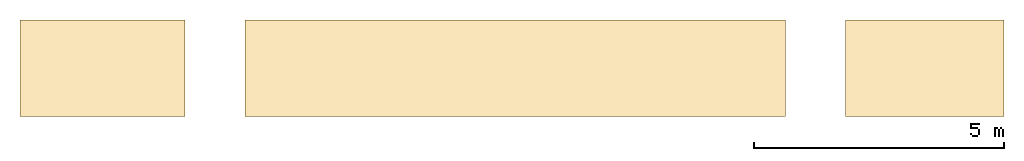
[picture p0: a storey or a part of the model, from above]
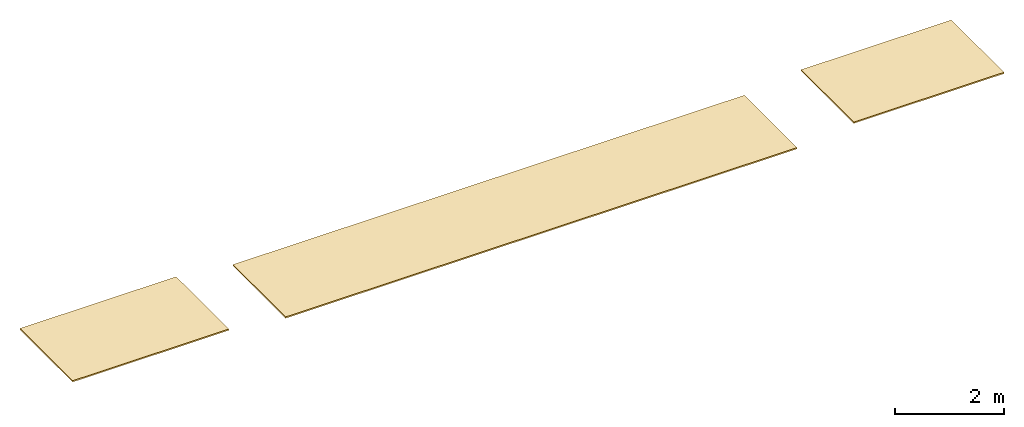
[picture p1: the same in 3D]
Properties of the parts of a building model (IFC2X3), part 1 of 3

# File
Description: ViewDefinition [CoordinationView]
File name: gmtio-a-200-1-0001.ifc (Edited by Naviate Simple BIM 2022 version 6)
Time: 2026-03-17T17:15:05+01:00
Written by: ODA SDAI 24.12
Made in: Autodesk Revit 25.4.20.11 (ENU) - IFC 25.4.0.27

# IfcProject, A181143
LongName: T2; Phase: Detaljprosjekt

# IfcSite (7)
Name | RefLatitude | RefLongitude | RefElevation (mm) | Reference latitude | Reference elevation | Reference longitude
ENGM | 33, 12, 51, 119999 | -97, -7, -51, -239999 | -4.85124e-10
Gardermoen
ENGM | 33, 12, 51, 119999 | -97, -7, -51, -239999 | 0 | 33, 12, 51, 119999 | 0 | -97, -7, -51, -239999 | MagiCAD Pset_Site - Name: ENGM
ENGM | 59, 54, 49, 759826 | 10, 44, 19, 467315 | 0 | 59, 54, 49, 759826 | 0 | 10, 44, 19, 467315 | MagiCAD Pset_Site - Name: ENGM
ENGM | 42, 24, 53, 508911 | -71, -15, -29, -58837 | 0 | 42, 24, 53, 508911 | 0 | -71, -15, -29, -58837 | MagiCAD Pset_Site - Name: ENGM
Default | 59, 54, 57, 599999 | 10, 44, 59, 999999 | 0
 | 33, 12, 51, 119998 | -97, -7, -51, -239998 | 0 | 33, 12, 51, 119998 | 0 | -97, -7, -51, -239998

# IfcBuilding (7)
Name
TI | LongName: TI; Pset_BuildingCommon - BuildingID: TI; NumberOfStoreys: 15
TI
3 x TI | MagiCAD Pset_Building - Building name: TI
 | Pset_BuildingCommon - NumberOfStoreys: 3; Pset_ProductRequirements - Category: Project Information
mc-building

# IfcBuildingStorey (12)
Name | In | Elevation (mm) | Name
D | TI | 0
F | TI | 0
3 x Nivå F | TI | 210900 | Nivå F
Nivå D + 1,2 m | TI | 205200 | Nivå D + 1,2 m
2 x Nivå E | TI | 207370 | Nivå E
Nivå D | TI | 204000 | Nivå D
Nivå D | mc-building | 204000 | Nivå D
Nivå D + 1,2 m | mc-building | 205200 | Nivå D + 1,2 m
Nivå F -0,7 | mc-building | 210200 | Nivå F -0,7

# IfcBuildingStorey: Level:8mm Head, Nivå E
LongName: Nivå E; Elevation: 207370 mm
Pset_ProductRequirements - Name: Nivå E; Category: Levels
Pset_AirSideSystemInformation - Name: Nivå E

# IfcBuildingStorey: Level:T2 - Kote (3)
In: TI
Name | LongName | Elevation (mm) | Pset_ProductRequirements, Name | Pset_ProductRequirements, sets with these values
Nivå D | Nivå D | 204000 | Pset_AirSideSystemInformation - Name: Nivå D; sets with these values: 2
Nivå F | Nivå F | 210900 | Nivå F | 2
Nivå G - 2,0m | Nivå G - 2,0m | 213700 | Nivå G - 2,0m | 2

# IfcBeam: DLB500*1500-900*1235*880, PREFABBJELKE
In: F
Description: DLB500*1500-900*1235*880
ePset_SimplebimBasicQuantities - Area, sides, net (Simplebim): 2.27588 m2; Volume, net (Simplebim): 0.189349 m3; Weight, as steel (Simplebim): 1486.39 kg; Width (Simplebim): 383 mm; Length (Simplebim): 900 mm; Height (Simplebim): 780 mm
AVINOR - 08_Status: S4; 07_Fase: F40; 06_Omrade: TI; 05_ID-nummer: +TI=223.007; 03_Ansvar: 72242; 04_Kontrakt: 72242; 02_Prosjekt: T20100; 01_Lufthavnkode: ENGM
Tekla Common - Name: PREFABBJELKE; Bottom elevation: +209.180; Grade: C45/55; Profile: DLB500*1500-900*1235*880; Assembly mark: PB-277; Part mark: Concrete-7649; Top elevation: +210.680; Class: 130
ePset_Simplebim - Assembly Level: Leaf
ePset_LocationTool - Splitting: RESULT
Pset_BeamCommon - LoadBearing: no; Reference: Concrete-7649

# IfcBeam: GRID:A255 - Opphengsgrid - Profil med deksel over og under (5)
In: Nivå F
Type - PredefinedType: BEAM; Material: Default, Metal - Steel
Type - Pset_BeamCommon - LoadBearing: yes
Pset_QuantityTakeOff - Reference: A255 - Opphengsgrid - Profil med deksel over og under; sets with these values: 2
AVINOR - 08_Status: S4; 07_Fase: F90; 05_ID-nummer: +TI=255.002; 06_Omrade: TI; 03_Ansvar: 72717; 02_Prosjekt: x; 01_Lufthavnkode: ENGM
ePset_LocationTool - Splitting: ORIGINAL
Pset_BeamCommon - Reference: A255 - Opphengsgrid - Profil med deksel over og under; IsExternal: no; Slope: 0 deg
ePset_Simplebim - Assembly Level: Leaf
ePset_SimplebimBasicQuantities - Width (Simplebim): 40 mm; Height (Simplebim): 96 mm
Name (GRID:A255 - Opphengsgrid - Profil med deksel over og under:...) | Span (mm) = Length (Simplebim) (mm) | Volume, net (Simplebim) (m3) | Weight, as steel (Simplebim) (kg) | Area, sides, net (Simplebim) (m2)
64454443 | 16817.8 | 0.011563 | 90.7693 | 11.937
64454517 | 17918.5 | 0.0123197 | 96.7096 | 12.7182
66954951 | 15717.2 | 0.0108062 | 84.829 | 11.1559
66954953 | 14616.6 | 0.0100495 | 78.8887 | 10.3748
67121430 | 18774.5 | 0.0129083 | 101.33 | 13.3257

# IfcBeam: IPE140 (3)
In: F
Description: IPE140; Material: STEEL/S355
ePset_Simplebim - Assembly Level: Leaf
ePset_SimplebimBasicQuantities - Width (Simplebim): 73 mm; Height (Simplebim): 140 mm
AVINOR - 08_Status: S4; 07_Fase: F90; 06_Omrade: TI; 05_ID-nummer: +TI=221.038; 04_Kontrakt: 72717; 02_Prosjekt: T20100; 03_Ansvar: 72101; 01_Lufthavnkode: ENGM
Tekla Quantity - Width: 73 mm; Heigth: 140 mm
ePset_LocationTool - Splitting: ORIGINAL
Pset_BeamCommon - LoadBearing: no
Tekla Common - Grade: S355; Name: STÅLBJELKE; Profile: IPE140; Class: 330
Name | Area, sides, net (Simplebim) (m2) | Volume, net (Simplebim) (m3) | Weight, as steel (Simplebim) (kg) = WEIGTH_NET (kg) | Length (Simplebim) (mm) = Length (mm) | VOLUME_GROSS (m3) | WEIGTH_GROSS (kg) | AREA_NET (m2) | VOLUME_NET (m3) | AREA_GROSS (m2) | Reference = Part mark | Top elevation | Assembly mark | Bottom elevation
STÅLBJELKE | 0.0988618 | 0.000272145 | 2.13634 | 170.033 | 0.00028 | 2.18901 | 0.09885 | 0.00026 | 0.09369 | DSB-0(?) | +213.578 | SS-0(?) | +213.438
STÅLBJELKE | 0.764585 | 0.0021659 | 17.0023 | 1363.01 | 0.00224 | 17.5474 | 0.76459 | 0.00217 | 0.75102 | DSB-24028(?) | +213.578 | SB-14382(?) | +213.438
STÅLBJELKE | 1.37537 | 0.00390368 | 30.6439 | 2438.98 | 0.00399 | 31.3994 | 1.37537 | 0.0039 | 1.34388 | DSB-19527(?) | +213.438 | SB-11779(?) | +213.298

# IfcBeam: L150*100*10 (2)
In: F
Description: L150*100*10; Material: STEEL/S355J0
ePset_LocationTool - Splitting: ORIGINAL
ePset_SimplebimBasicQuantities - Length (Simplebim): 128.286 mm; Weight, as steel (Simplebim): 2.05585 kg; Volume, net (Simplebim): 0.000261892 m3; Width (Simplebim): 119.998 mm; Height (Simplebim): 100 mm; Area, sides, net (Simplebim): 0.0591433 m2
Tekla Quantity - Heigth: 128.286 mm; Length: 119.998 mm; VOLUME_GROSS: 0.00028 m3; AREA_NET: 0.05914 m2; AREA_GROSS: 0.05868 m2; WEIGTH_NET: 2.05585 kg; VOLUME_NET: 0.00026 m3; Width: 100 mm; WEIGTH_GROSS: 2.27961 kg
ePset_Simplebim - Assembly Level: Leaf
AVINOR - 08_Status: S4; 07_Fase: F90; 06_Omrade: TI; 05_ID-nummer: +TI=221.038; 04_Kontrakt: 72717; 02_Prosjekt: T20100; 03_Ansvar: 72101; 01_Lufthavnkode: ENGM
Tekla Common - Bottom elevation: +213.578; Name: STÅLBJELKE; Assembly mark: SB-11789(?); Profile: L150*100*10; Grade: S355J0; Part mark: DSB-0(?); Top elevation: +213.678; Class: 330
Pset_BeamCommon - LoadBearing: no; Reference: DSB-0(?)

# IfcBeam: L150*90*9 (2)
In: F
Description: L150*90*9; Material: STEEL/S355
ePset_LocationTool - Splitting: ORIGINAL
ePset_Simplebim - Assembly Level: Leaf
Tekla Common - Grade: S355; Name: STÅLBJELKE; Bottom elevation: +213.405; Top elevation: +213.495; Profile: L150*90*9; Class: 330
AVINOR - 04_Kontrakt: 72253; 05_ID-nummer: +TI=221.025; 08_Status: S4; 07_Fase: F90; 06_Omrade: TI; 02_Prosjekt: T20100; 03_Ansvar: 72101; 01_Lufthavnkode: ENGM
ePset_SimplebimBasicQuantities - Height (Simplebim): 90 mm
Pset_BeamCommon - LoadBearing: no
Tekla Quantity - VOLUME_NET: 0.00034 m3; AREA_NET: 0.08296 m2; VOLUME_GROSS: 0.00039 m3; Width: 90 mm; AREA_GROSS: 0.09536 m2
Name | Assembly mark | Part mark = Reference | Width (Simplebim) (mm) = Heigth (mm) | Weight, as steel (Simplebim) (kg) = WEIGTH_NET (kg) | Volume, net (Simplebim) (m3) | Length (Simplebim) (mm) = Length (mm) | Area, sides, net (Simplebim) (m2) | WEIGTH_GROSS (kg)
STÅLBJELKE | SB-14628(?) | DSB-24528(?) | 147.671 | 2.6797 | 0.000341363 | 189.996 | 0.0829498 | 3.10076
STÅLBJELKE | SB-14629(?) | DSB-24529(?) | 147.673 | 2.67982 | 0.000341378 | 190.008 | 0.0829534 | 3.10097

# IfcBeam: L75*8 (6)
In: F
Description: L75*8; Material: STEEL/S355J0
Tekla Common - Bottom elevation: +213.578; Profile: L75*8; Name: STÅLBJELKE; Top elevation: +213.653; Grade: S355J0; Part mark: DSB-0(?); Class: 330
ePset_Simplebim - Assembly Level: Leaf
Tekla Quantity - Heigth: 75 mm; Width: 75 mm
AVINOR - 08_Status: S4; 07_Fase: F90; 06_Omrade: TI; 05_ID-nummer: +TI=221.038; 04_Kontrakt: 72717; 02_Prosjekt: T20100; 03_Ansvar: 72101; 01_Lufthavnkode: ENGM
ePset_SimplebimBasicQuantities - Height (Simplebim): 75 mm; Width (Simplebim): 75 mm
Pset_BeamCommon - LoadBearing: no; Reference: DSB-0(?)
ePset_LocationTool - Splitting: ORIGINAL
Name | Assembly mark | VOLUME_NET (m3) | VOLUME_GROSS (m3) | AREA_GROSS (m2) | WEIGTH_GROSS (kg) | WEIGTH_NET (kg) = Weight, as steel (Simplebim) (kg) | Length (mm) = Length (Simplebim) (mm) | AREA_NET (m2) | Area, sides, net (Simplebim) (m2) | Volume, net (Simplebim) (m3)
STÅLBJELKE | SB-11777(?) | 0.00022 | 0.00022 | 0.0582 | 1.80556 | 1.78358 | 200.006 | 0.06227 | 0.0622739 | 0.000227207
STÅLBJELKE | SB-11777(?) | 0.00017 | 0.00017 | 0.04365 | 1.35411 | 1.33762 | 149.998 | 0.04727 | 0.0472715 | 0.000170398
2 x STÅLBJELKE | SB-11789(?) | 0.00017 | 0.00017 | 0.04365 | 1.35411 | 1.33762 | 149.998 | 0.04727 | 0.0472715 | 0.000170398
STÅLBJELKE | SB-11779(?) | 0.00011 | 0.00013 | 0.0291 | 0.90275 | 0.89176 | 100 | 0.03227 | 0.032272 | 0.0001136
STÅLBJELKE | SB-11779(?) | 0.00011 | 0.00011 | 0.0291 | 0.90275 | 0.89176 | 100 | 0.03227 | 0.032272 | 0.0001136

# IfcBeam: L90*150*9 (2)
In: F
Description: L90*150*9; Material: STEEL/S355
ePset_SimplebimBasicQuantities - Volume, net (Simplebim): 0.000341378 m3; Area, sides, net (Simplebim): 0.0829534 m2; Length (Simplebim): 190.008 mm; Width (Simplebim): 147.673 mm; Weight, as steel (Simplebim): 2.67982 kg; Height (Simplebim): 90 mm
Tekla Quantity - Length: 190.008 mm; VOLUME_NET: 0.00034 m3; AREA_NET: 0.08296 m2; Width: 147.673 mm; VOLUME_GROSS: 0.00039 m3; WEIGTH_GROSS: 3.10097 kg; WEIGTH_NET: 2.67982 kg; Heigth: 90 mm; AREA_GROSS: 0.09536 m2
ePset_Simplebim - Assembly Level: Leaf
Pset_BeamCommon - LoadBearing: no
AVINOR - 04_Kontrakt: 72253; 05_ID-nummer: +TI=221.025; 08_Status: S4; 07_Fase: F90; 06_Omrade: TI; 02_Prosjekt: T20100; 03_Ansvar: 72101; 01_Lufthavnkode: ENGM
ePset_LocationTool - Splitting: ORIGINAL
Tekla Common - Grade: S355; Bottom elevation: +213.805; Top elevation: +213.895; Name: STÅLBJELKE; Profile: L90*150*9; Class: 330
Name | Reference = Part mark | Assembly mark
STÅLBJELKE | DSB-24527(?) | SB-14627(?)
STÅLBJELKE | DSB-24526(?) | SB-14626(?)

# IfcBeam: L90*9 (148)
In: F
Description: L90*9; Material: STEEL/S355
ePset_SimplebimBasicQuantities - Height (Simplebim): 90 mm
ePset_Simplebim - Assembly Level: Leaf
ePset_LocationTool - Splitting: ORIGINAL
AVINOR - 04_Kontrakt: 72253; 05_ID-nummer: +TI=221.025; 08_Status: S4; 07_Fase: F90; 06_Omrade: TI; 02_Prosjekt: T20100; 03_Ansvar: 72101; 01_Lufthavnkode: ENGM
Tekla Common - Profile: L90*9; Grade: S355; Name: STÅLBJELKE; Class: 330
Tekla Quantity - VOLUME_NET: 0.00022 m3
Pset_BeamCommon - LoadBearing: no
Name | Volume, net (Simplebim) (m3) | Weight, as steel (Simplebim) (kg) | Width (Simplebim) (mm) | Area, sides, net (Simplebim) (m2) | Length (Simplebim) (mm) | Assembly mark | Part mark = Reference | Bottom elevation | Top elevation | AREA_GROSS (m2) | VOLUME_GROSS (m3) | Heigth (mm) | WEIGTH_GROSS (kg) | Width (mm) | AREA_NET (m2) | Length (mm) | WEIGTH_NET (kg)
STÅLBJELKE | 0.000226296 | 1.77642 | 80.3791 | 0.0561683 | 190.006 | SB-11832(?) | DSB-19626(?) | +213.405 | +213.495 | 0.06669 | 0.00028 | 80.3791 | 2.3119 | 90 | 0.05617 | 190.006 | 1.77642
STÅLBJELKE | 0.000226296 | 1.77642 | 80.3791 | 0.0561683 | 190.006 | SB-11833(?) | DSB-19627(?) | +213.805 | +213.895 | 0.06669 | 0.00028 | 90 | 2.3119 | 80.3791 | 0.05617 | 190.006 | 1.77642
STÅLBJELKE | 0.000226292 | 1.77639 | 80.3766 | 0.0561673 | 190.006 | SB-11833(?) | DSB-19627(?) | +213.405 | +213.495 | 0.06669 | 0.00028 | 80.3766 | 2.3119 | 90 | 0.05617 | 190.006 | 1.77639
STÅLBJELKE | 0.000226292 | 1.77639 | 80.3766 | 0.0561673 | 190.006 | SB-11832(?) | DSB-19626(?) | +213.805 | +213.895 | 0.06669 | 0.00028 | 90 | 2.3119 | 80.3766 | 0.05617 | 190.006 | 1.77639
29 x STÅLBJELKE | 0.00023085 | 1.81217 | 90 | 0.057078 | 150 | SB-11830(?) | DSB-19624(?) | +213.405 | +213.495 | 0.05265 | 0.00022 | 90 | 1.82506 | 90 | 0.05708 | 149.995 | 1.81211
29 x STÅLBJELKE | 0.00023085 | 1.81217 | 90 | 0.057078 | 150 | SB-11830(?) | DSB-19624(?) | +213.805 | +213.895 | 0.05265 | 0.00022 | 90 | 1.82506 | 90 | 0.05708 | 149.995 | 1.81211
7 x STÅLBJELKE | 0.00023085 | 1.81217 | 90 | 0.057078 | 150 | SB-11830(?) | DSB-19624(?) | +213.405 | +213.495 | 0.05265 | 0.00022 | 90 | 1.82529 | 90 | 0.05708 | 150.014 | 1.81234
7 x STÅLBJELKE | 0.00023085 | 1.81217 | 90 | 0.057078 | 150 | SB-11830(?) | DSB-19624(?) | +213.805 | +213.895 | 0.05265 | 0.00022 | 90 | 1.82529 | 90 | 0.05708 | 150.014 | 1.81234
36 x STÅLBJELKE | 0.00023085 | 1.81217 | 90 | 0.057078 | 150 | SB-11830(?) | DSB-19624(?) | +213.405 | +213.495 | 0.05265 | 0.00022 | 90 | 1.82512 | 90 | 0.05708 | 150 | 1.81217
36 x STÅLBJELKE | 0.00023085 | 1.81217 | 90 | 0.057078 | 150 | SB-11830(?) | DSB-19624(?) | +213.805 | +213.895 | 0.05265 | 0.00022 | 90 | 1.82512 | 90 | 0.05708 | 150 | 1.81217

# IfcBeam: PL10*180, STÅLBJELKE
In: F
Description: PL10*180; Material: STEEL/S355J0
Tekla Common - Name: STÅLBJELKE; Top elevation: +213.693; Bottom elevation: +213.513; Grade: S355J0; Part mark: DSB-0(?); Profile: PL10*180; Class: 330; Assembly mark: SB-11777(?)
ePset_SimplebimBasicQuantities - Area, sides, net (Simplebim): 0.0529974 m2; Weight, as steel (Simplebim): 1.8368 kg; Height (Simplebim): 180 mm; Width (Simplebim): 10 mm; Length (Simplebim): 129.993 mm; Volume, net (Simplebim): 0.000233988 m3
ePset_Simplebim - Assembly Level: Leaf
AVINOR - 08_Status: S4; 07_Fase: F90; 06_Omrade: TI; 05_ID-nummer: +TI=221.038; 04_Kontrakt: 72717; 02_Prosjekt: T20100; 03_Ansvar: 72101; 01_Lufthavnkode: ENGM
Pset_BeamCommon - LoadBearing: no; Reference: DSB-0(?)
ePset_LocationTool - Splitting: ORIGINAL
Tekla Quantity - VOLUME_NET: 0.00022 m3; VOLUME_GROSS: 0.00022 m3; AREA_GROSS: 0.053 m2; AREA_NET: 0.053 m2; Width: 10 mm; Heigth: 180 mm; WEIGTH_GROSS: 1.8368 kg; WEIGTH_NET: 1.8368 kg; Length: 129.993 mm

# IfcBeam: PL10*490 (10)
In: F
Description: PL10*490; Material: STEEL/S355
ePset_SimplebimBasicQuantities - Height (Simplebim): 490 mm
Pset_BeamCommon - LoadBearing: no
ePset_Simplebim - Assembly Level: Leaf
Tekla Quantity - Heigth: 490 mm
ePset_LocationTool - Splitting: ORIGINAL
AVINOR - 04_Kontrakt: 72253; 05_ID-nummer: +TI=221.025; 08_Status: S4; 07_Fase: F90; 06_Omrade: TI; 02_Prosjekt: T20100; 03_Ansvar: 72101; 01_Lufthavnkode: ENGM
Tekla Common - Grade: S355; Top elevation: +213.895; Name: STÅLBJELKE; Profile: PL10*490; Bottom elevation: +213.405; Class: 330
Name | Volume, net (Simplebim) (m3) | Width (Simplebim) (mm) | Length (Simplebim) (mm) | Area, sides, net (Simplebim) (m2) | Weight, as steel (Simplebim) (kg) | Reference = Part mark | Length (mm) | WEIGTH_NET (kg) | AREA_GROSS (m2) | AREA_NET (m2) | Width (mm) | VOLUME_NET (m3) | VOLUME_GROSS (m3) | WEIGTH_GROSS (kg) | Assembly mark
STÅLBJELKE | 0.00416928 | 200.017 | 619.575 | 0.866946 | 32.7289 | DSS-5676(?) | 936.263 | 32.7285 | 0.94606 | 0.86695 | 10.0076 | 0.00416 | 0.00458 | 36.0133 | SS-8909(?)
STÅLBJELKE | 0.0038293 | 200.017 | 619.575 | 0.798947 | 30.06 | DSS-5677(?) | 936.263 | 30.0606 | 0.94606 | 0.79895 | 10.0076 | 0.00383 | 0.00458 | 36.0133 | SS-8910(?)
STÅLBJELKE | 0.021315 | 10 | 4350 | 4.3598 | 167.323 | DSS-5860(?) | 4350 | 167.323 | 4.3598 | 4.3598 | 10 | 0.02131 | 0.0213 | 167.323 | SS-9019(?)
2 x STÅLBJELKE | 0.02156 | 10 | 4400 | 4.4098 | 169.246 | DSS-5861(?) | 4400 | 169.246 | 4.4098 | 4.4098 | 10 | 0.02156 | 0.02156 | 169.246 | SS-9020(?)
STÅLBJELKE | 0.021315 | 10 | 4350 | 4.3598 | 167.323 | DSS-5860(?) | 4350 | 167.323 | 4.3598 | 4.3598 | 10 | 0.02131 | 0.02132 | 167.323 | SS-9019(?)
2 x STÅLBJELKE | 0.0208005 | 10 | 4245 | 4.2548 | 163.284 | DSS-5858(?) | 4245 | 163.284 | 4.2548 | 4.2548 | 10 | 0.0208 | 0.0208 | 163.284 | SS-9017(?)
2 x STÅLBJELKE | 0.0206045 | 10 | 4205 | 4.2148 | 161.745 | DSS-5857(?) | 4205 | 161.745 | 4.2148 | 4.2148 | 10 | 0.0206 | 0.0206 | 161.745 | SS-9016(?)

# IfcBeam: PL8*100 (11)
In: F
Description: PL8*100; Material: STEEL/S355
Tekla Common - Grade: S355; Name: STÅLBJELKE; Top elevation: +213.745; Profile: PL8*100; Bottom elevation: +213.737; Part mark: DSB-14986(?); Class: 330
Pset_BeamCommon - LoadBearing: no; Reference: DSB-14986(?)
ePset_LocationTool - Splitting: ORIGINAL
ePset_Simplebim - Assembly Level: Leaf
AVINOR - 04_Kontrakt: 72253; 05_ID-nummer: +TI=221.025; 08_Status: S4; 07_Fase: F90; 06_Omrade: TI; 02_Prosjekt: T20100; 03_Ansvar: 72101; 01_Lufthavnkode: ENGM
ePset_SimplebimBasicQuantities - Area, sides, net (Simplebim): 0.0448 m2; Volume, net (Simplebim): 0.00016 m3; Height (Simplebim): 8 mm; Width (Simplebim): 100 mm; Length (Simplebim): 200 mm; Weight, as steel (Simplebim): 1.256 kg
Tekla Quantity - AREA_NET: 0.0448 m2; VOLUME_GROSS: 0.00015 m3; VOLUME_NET: 0.00015 m3; Width: 8 mm; Heigth: 100 mm; Length: 200 mm; WEIGTH_NET: 1.256 kg; WEIGTH_GROSS: 1.256 kg; AREA_GROSS: 0.02 m2
Name | Assembly mark
2 x STÅLBJELKE | SS-7605(?)
STÅLBJELKE | SS-7611(?)
5 x STÅLBJELKE | SB-9013(?)
3 x STÅLBJELKE | SS-7612(?)

# IfcBeam: PL8*30 (4)
In: F
Description: PL8*30; Material: STEEL/S355
ePset_SimplebimBasicQuantities - Height (Simplebim): 126.2 mm; Weight, as steel (Simplebim): 0.231481 kg; Volume, net (Simplebim): 0.000029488 m3; Width (Simplebim): 8 mm; Length (Simplebim): 30 mm; Area, sides, net (Simplebim): 0.00977747 m2
Tekla Common - Profile: PL8*30; Grade: S355; Name: STÅLBJELKE; Part mark: DSB-0(?); Class: 330
ePset_Simplebim - Assembly Level: Leaf
AVINOR - 08_Status: S4; 07_Fase: F90; 06_Omrade: TI; 05_ID-nummer: +TI=221.038; 04_Kontrakt: 72717; 02_Prosjekt: T20100; 03_Ansvar: 72101; 01_Lufthavnkode: ENGM
ePset_LocationTool - Splitting: ORIGINAL
Pset_BeamCommon - LoadBearing: no; Reference: DSB-0(?)
Tekla Quantity - Length: 126.2 mm; WEIGTH_NET: 0.23148 kg; AREA_GROSS: 0.00379 m2; Width: 8 mm; Heigth: 30 mm; WEIGTH_GROSS: 0.23776 kg; AREA_NET: 0.00978 m2; VOLUME_GROSS: 0.00003 m3; VOLUME_NET: 0.00003 m3
Name | Assembly mark | Bottom elevation | Top elevation
2 x STÅLBJELKE | SB-14382(?) | +213.445 | +213.571
2 x STÅLBJELKE | SB-11779(?) | +213.305 | +213.431

# IfcBeam: PL8*85, STÅLBJELKE
In: F
Description: PL8*85; Material: STEEL/S355
ePset_SimplebimBasicQuantities - Area, sides, net (Simplebim): 0.05623 m2; Volume, net (Simplebim): 0.0002006 m3; Weight, as steel (Simplebim): 1.57471 kg; Height (Simplebim): 8 mm; Width (Simplebim): 85 mm; Length (Simplebim): 295 mm
ePset_Simplebim - Assembly Level: Leaf
AVINOR - 08_Status: S4; 07_Fase: F90; 06_Omrade: TI; 05_ID-nummer: +TI=221.038; 04_Kontrakt: 72717; 02_Prosjekt: T20100; 03_Ansvar: 72101; 01_Lufthavnkode: ENGM
Tekla Common - Grade: S355; Profile: PL8*85; Name: STÅLBJELKE; Assembly mark: SS-0(?); Part mark: DSB-0(?); Top elevation: +213.298; Class: 330; Bottom elevation: +213.290
Pset_BeamCommon - LoadBearing: no; Reference: DSB-0(?)
ePset_LocationTool - Splitting: ORIGINAL
Tekla Quantity - AREA_NET: 0.05623 m2; VOLUME_GROSS: 0.0002 m3; VOLUME_NET: 0.0002 m3; AREA_GROSS: 0.05622 m2; WEIGTH_GROSS: 1.57471 kg; WEIGTH_NET: 1.57471 kg; Width: 8 mm; Heigth: 85 mm; Length: 295 mm

# IfcBeam: RHS100*8, STÅLBJELKE
In: F
Description: RHS100*8; Material: STEEL/S355
Tekla Quantity - AREA_NET: 5.5511 m2; WEIGTH_GROSS: 317.524 kg; VOLUME_GROSS: 0.04045 m3; WEIGTH_NET: 320.527 kg; AREA_GROSS: 5.32369 m2; Length: 13900 mm; Heigth: 100 mm; Width: 100 mm; VOLUME_NET: 0.04083 m3
ePset_Simplebim - Assembly Level: Leaf
ePset_LocationTool - Splitting: ORIGINAL
Pset_BeamCommon - Reference: DSS-6695(?); LoadBearing: no
Tekla Common - Part mark: DSS-6695(?); Grade: S355; Top elevation: +213.895; Name: STÅLBJELKE; Profile: RHS100*8; Bottom elevation: +213.795; Assembly mark: SS-8144(?); Class: 330
ePset_SimplebimBasicQuantities - Weight, as steel (Simplebim): 320.527 kg; Length (Simplebim): 13900 mm; Width (Simplebim): 100 mm; Height (Simplebim): 100 mm; Volume, net (Simplebim): 0.0408315 m3; Area, sides, net (Simplebim): 10.214 m2
AVINOR - 04_Kontrakt: 72253; 05_ID-nummer: +TI=221.025; 08_Status: S4; 07_Fase: F90; 06_Omrade: TI; 02_Prosjekt: T20100; 03_Ansvar: 72101; 01_Lufthavnkode: ENGM

# IfcBeam: RHS120*80*6.3 (3)
In: F
Description: RHS120*80*6.3; Material: STEEL/S355
ePset_SimplebimBasicQuantities - Height (Simplebim): 120 mm; Width (Simplebim): 80 mm
Tekla Quantity - Width: 80 mm; Heigth: 120 mm
ePset_LocationTool - Splitting: ORIGINAL
ePset_Simplebim - Assembly Level: Leaf
Tekla Common - Grade: S355; Bottom elevation: +213.578; Name: STÅLBJELKE; Top elevation: +213.698; Profile: RHS120*80*6.3; Class: 330
AVINOR - 08_Status: S4; 07_Fase: F90; 06_Omrade: TI; 05_ID-nummer: +TI=221.038; 04_Kontrakt: 72717; 02_Prosjekt: T20100; 03_Ansvar: 72101; 01_Lufthavnkode: ENGM
Pset_BeamCommon - LoadBearing: no
Name | Weight, as steel (Simplebim) (kg) = WEIGTH_NET (kg) | Area, sides, net (Simplebim) (m2) | Length (Simplebim) (mm) = Length (mm) | Volume, net (Simplebim) (m3) | WEIGTH_GROSS (kg) | AREA_NET (m2) | VOLUME_NET (m3) | AREA_GROSS (m2) | VOLUME_GROSS (m3) | Part mark = Reference | Assembly mark
STÅLBJELKE | 54.9469 | 2.22682 | 2964.38 | 0.0069996 | 54.4526 | 1.1751 | 0.007 | 1.14425 | 0.00695 | DSB-19527(?) | SB-11779(?)
STÅLBJELKE | 63.0256 | 2.55414 | 3430.87 | 0.00802874 | 63.0216 | 1.34783 | 0.00803 | 1.32432 | 0.00804 | DSB-19525(?) | SB-11777(?)
STÅLBJELKE | 215.516 | 8.72097 | 11657.8 | 0.0274542 | 214.142 | 4.60209 | 0.02745 | 4.4999 | 0.02728 | DSB-19537(?) | SB-11789(?)

# IfcBeam: RHS150*100*8 (11)
In: F
Description: RHS150*100*8
ePset_SimplebimBasicQuantities - Height (Simplebim): 150 mm; Width (Simplebim): 100 mm
Pset_BeamCommon - LoadBearing: no
ePset_Simplebim - Assembly Level: Leaf
AVINOR - 04_Kontrakt: 72253; 05_ID-nummer: +TI=221.025; 08_Status: S4; 07_Fase: F90; 06_Omrade: TI; 02_Prosjekt: T20100; 03_Ansvar: 72101; 01_Lufthavnkode: ENGM
Tekla Common - Grade: S355; Name: STÅLBJELKE; Profile: RHS150*100*8; Class: 330
Name | Material | Area, sides, net (Simplebim) (m2) | Volume, net (Simplebim) (m3) | Length (Simplebim) (mm) | Weight, as steel (Simplebim) (kg) | Reference = Part mark | AREA_GROSS (m2) | VOLUME_GROSS (m3) | Length (mm) | VOLUME_NET (m3) | AREA_NET (m2) | WEIGTH_GROSS (kg) | Width (mm) | Heigth (mm) | WEIGTH_NET (kg) | Top elevation | Bottom elevation | Assembly mark | Splitting
4 x STÅLBJELKE | STEEL/S355 | 4.12589 | 0.0164736 | 4400 | 129.318 | DSS-6588(?) | 2.1252 | 0.01631 | 4400 | 0.01647 | 2.17917 | 128.143 | 100 | 150 | 129.318 | +213.555 | +213.405 | SS-9335(?) | ORIGINAL
STÅLBJELKE | STEEL/S355 | 16.8555 | 0.067392 | 18000 | 529.027 | DSS-6587(?) | 8.694 | 0.06678 | 18000 | 0.06739 | 8.90255 | 524.223 | 100 | 150 | 529.027 | +213.895 | +213.745 | SS-9334(?) | ORIGINAL
2 x STÅLBJELKE | STEEL/S355 | 3.94337 | 0.0157435 | 4205 | 123.587 | DSS-6586(?) | 2.03101 | 0.0156 | 4205 | 0.01574 | 2.08276 | 122.464 | 100 | 150 | 123.587 | +213.555 | +213.405 | SS-9333(?) | ORIGINAL
2 x STÅLBJELKE | STEEL/S355 | 3.98081 | 0.0158933 | 4245 | 124.762 | DSS-6585(?) | 2.05034 | 0.01575 | 4245 | 0.0159 | 2.10254 | 123.629 | 100 | 150 | 124.762 | +213.555 | +213.405 | SS-9332(?) | ORIGINAL
2 x STÅLBJELKE |  | 8.22658 | 0.0328757 | 8796 | 258.074 | DSS-6583(?) |  |  |  |  |  |  |  |  |  | +213.895 | +213.745 | SS-9330(?) | RESULT

# IfcBeam: RHS80*6.3, STÅLBJELKE
In: F
Description: RHS80*6.3; Material: STEEL/S355
ePset_SimplebimBasicQuantities - Weight, as steel (Simplebim): 2.01195 kg; Length (Simplebim): 80 mm; Width (Simplebim): 80 mm; Height (Simplebim): 138 mm; Area, sides, net (Simplebim): 0.0850793 m2; Volume, net (Simplebim): 0.000256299 m3
ePset_Simplebim - Assembly Level: Leaf
AVINOR - 08_Status: S4; 07_Fase: F90; 06_Omrade: TI; 05_ID-nummer: +TI=221.038; 04_Kontrakt: 72717; 02_Prosjekt: T20100; 03_Ansvar: 72101; 01_Lufthavnkode: ENGM
Tekla Common - Grade: S355; Top elevation: +213.578; Profile: RHS80*6.3; Name: STÅLBJELKE; Assembly mark: SB-11789(?); Part mark: DSB-0(?); Bottom elevation: +213.440; Class: 330
Tekla Quantity - AREA_NET: 0.04618 m2; AREA_GROSS: 0.04223 m2; VOLUME_GROSS: 0.00025 m3; WEIGTH_GROSS: 1.99327 kg; VOLUME_NET: 0.00026 m3; Heigth: 80 mm; Width: 80 mm; Length: 138 mm; WEIGTH_NET: 2.01195 kg
Pset_BeamCommon - LoadBearing: no; Reference: DSB-0(?)
ePset_LocationTool - Splitting: ORIGINAL

# IfcBuildingElementProxy (4)
ePset_Simplebim - Assembly Level: Leaf
Name | In | Splitting | Length (Simplebim) (mm) | Volume, net (Simplebim) (m3) | Height (Simplebim) (mm) | Thickness (Simplebim) (mm) | Area, largest surface, net (Simplebim) (m2)
Håndslukker | Nivå D + 1,2 m | ORIGINAL | 323.075 | 0.0130382 | 600.535 | 179.937 | 0.261216
Håndslukker | Nivå F -0,7 | ORIGINAL | 323.075 | 0.0130382 | 600.535 | 179.937 | 0.261216
11142925 | Nivå E | RESULT | 4565 | 0.0592184 | 20 | 2227 | 0.995706 | Pset_ProductRequirements - Category: Generic Models; Group: Model Group:TI-F15:11142849
11142729 | Nivå E | RESULT | 4483 | 0.00985515 | 70 | 2040 | 0.535907 | Pset_ProductRequirements - Category: Generic Models; Group: Model Group:TI-F14:11142709

# IfcBuildingElementProxy: A232 - Gulvluke_Installasjonsgulv:A253 - Gulvluke - Installasjonsgulv (5)
In: Nivå F
Type - Material: <Unnamed>
Pset_QuantityTakeOff - Reference: A253 - Gulvluke - Installasjonsgulv; sets with these values: 2
ePset_Simplebim - Assembly Level: Leaf
ePset_LocationTool - Splitting: ORIGINAL
ePset_SimplebimBasicQuantities - Area, largest surface, net (Simplebim): 0.0119 m2; Height (Simplebim): 5 mm; Length (Simplebim): 600 mm; Thickness (Simplebim): 600 mm; Volume, net (Simplebim): 0.0000595 m3
AVINOR - 08_Status: S4; 07_Fase: F40; 05_ID-nummer: +TI=254.001; 06_Omrade: TI; 03_Ansvar: 72243; 02_Prosjekt: T20100; 01_Lufthavnkode: ENGM
Name (A232 - Gulvluke_Installasjonsgulv:A253 - Gulvluke - Installasjonsgulv:...)
42271319
42272060
42272414
65143137
66647814

# IfcBuildingElementProxy: A234 - Gitter:A241 - Gitter 300 x 300_UK_2550 (8)
In: Nivå F
Type - Material: <Unnamed>
Pset_QuantityTakeOff - Reference: A241 - Gitter 300 x 300_UK_2550; sets with these values: 2
ePset_Simplebim - Assembly Level: Leaf
ePset_LocationTool - Splitting: ORIGINAL
AVINOR - 08_Status: S4; 07_Fase: F90; 05_ID-nummer: +TI=245.051; 06_Omrade: TI; 03_Ansvar: 72717; 02_Prosjekt: T20100; 01_Lufthavnkode: ENGM
ePset_SimplebimBasicQuantities - Height (Simplebim): 300 mm; Thickness (Simplebim): 300 mm
Name (A234 - Gitter:A241 - Gitter 300 x 300_UK_2550:...) | Area, largest surface, net (Simplebim) (m2) | Length (Simplebim) (mm) | Volume, net (Simplebim) (m3)
66487129 | 1.35 | 4500 | 0.405
66487155 | 1.35 | 4500 | 0.405
66487156 | 1.35 | 4500 | 0.405
66487158 | 1.35 | 4500 | 0.405
66487160 | 1.2915 | 4305 | 0.38745
66487162 | 1.28884 | 4296.15 | 0.386653
66487164 | 1.2915 | 4305 | 0.38745
66487165 | 1.30395 | 4346.49 | 0.391184

# IfcBuildingElementProxy: A253 - Gulvluke_varmefordeler:A253 - GulvLuke - Varmefordeler (4)
In: Nivå F
Type - Material: <Unnamed>
ePset_Simplebim - Assembly Level: Leaf
ePset_LocationTool - Splitting: ORIGINAL
Pset_QuantityTakeOff - Reference: A253 - GulvLuke - Varmefordeler; sets with these values: 2
ePset_SimplebimBasicQuantities - Area, largest surface, net (Simplebim): 0.0119 m2; Height (Simplebim): 5 mm; Length (Simplebim): 600 mm; Thickness (Simplebim): 600 mm; Volume, net (Simplebim): 0.0000595 m3
AVINOR - 08_Status: S4; 07_Fase: F40; 05_ID-nummer: +TI=254.001; 06_Omrade: TI; 03_Ansvar: 72243; 02_Prosjekt: T20100; 01_Lufthavnkode: ENGM
Name (A253 - Gulvluke_varmefordeler:A253 - GulvLuke - Varmefordeler:...)
65136963
65137130
66647865
66647868

# IfcBuildingElementProxy: A275 - Pylon - venstrehengslet:A275 - Pylon - venstrehengslet (4)
In: Nivå F
Type - Material: <Unnamed>
AVINOR - 08_Status: S4; 06_Omrade: TI; 02_Prosjekt: T20100; 07_Fase: F50; 03_Ansvar: OSL; 01_Lufthavnkode: ENGM
ePset_LocationTool - Splitting: ORIGINAL
ePset_SimplebimBasicQuantities - Area, largest surface, net (Simplebim): 1.78713 m2; Volume, net (Simplebim): 0.0408924 m3; Thickness (Simplebim): 195 mm; Length (Simplebim): 752 mm; Height (Simplebim): 2500 mm
ePset_Simplebim - Assembly Level: Leaf
Pset_QuantityTakeOff - Reference: A275 - Pylon - venstrehengslet; sets with these values: 2
Name (A275 - Pylon - venstrehengslet:A275 - Pylon - venstrehengslet:...)
68417630
68417802
68417976
68418150

# IfcBuildingElementProxy: A36 - Føringsskinner rullegitter:A36 - Føringsskinner rullegitter (16)
In: Nivå F
Type - Material: <Unnamed>
ePset_LocationTool - Splitting: ORIGINAL
Pset_QuantityTakeOff - Reference: A36 - Føringsskinner rullegitter; sets with these values: 2
ePset_Simplebim - Assembly Level: Leaf
ePset_SimplebimBasicQuantities - Volume, net (Simplebim): 0.00117 m3; Area, largest surface, net (Simplebim): 0.25 m2; Thickness (Simplebim): 38 mm; Length (Simplebim): 100 mm; Height (Simplebim): 2500 mm
AVINOR - 08_Status: S4; 07_Fase: F90; 05_ID-nummer: +TI=245.051; 06_Omrade: TI; 03_Ansvar: 72717; 02_Prosjekt: T20100; 01_Lufthavnkode: ENGM
Name (A36 - Føringsskinner rullegitter:A36 - Føringsskinner rullegitter:...)
62671053
62671054
62671055
62671056
62671057
62671058
62671059
62671060
62671061
62671062
62671063
62671065
62671069
62671070
62671071
62671073

# IfcBuildingElementProxy: HF - butikkfasader - vertikal skilt hjørne 1:HF - butikkfasader - vertikal skilt hjørne 1, HF - butikkfasader - vertikal skilt hjørne 1:HF - butikkfasader - vertikal skilt hjørne 1:60017706
In: Nivå F
Type - Material: <Unnamed>
Pset_BuildingElementProxyCommon - Reference: HF - butikkfasader - vertikal skilt hjørne 1; sets with these values: 2
ePset_LocationTool - Splitting: ORIGINAL
ePset_SimplebimBasicQuantities - Volume, net (Simplebim): 0.409252 m3; Length (Simplebim): 799.603 mm; Thickness (Simplebim): 260.002 mm; Area, largest surface, net (Simplebim): 1.9191 m2; Height (Simplebim): 2400 mm
ePset_Simplebim - Assembly Level: Leaf
AVINOR - 08_Status: S4; 07_Fase: F90; 06_Omrade: TI; 05_ID-nummer: +TI=241.025; 03_Ansvar: 72717; 02_Prosjekt: T20100; 01_Lufthavnkode: ENGM

# IfcBuildingElementProxy: HF - butikkfasader - vertikal skilt hjørne 2:HF - butikkfasader - vertikal skilt hjørne 1, HF - butikkfasader - vertikal skilt hjørne 2:HF - butikkfasader - vertikal skilt hjørne 1:60017721
In: Nivå F
Type - Material: <Unnamed>
Pset_BuildingElementProxyCommon - Reference: HF - butikkfasader - vertikal skilt hjørne 1; sets with these values: 2
ePset_SimplebimBasicQuantities - Thickness (Simplebim): 260.002 mm; Volume, net (Simplebim): 0.409176 m3; Height (Simplebim): 2400 mm; Length (Simplebim): 799.461 mm; Area, largest surface, net (Simplebim): 1.91865 m2
ePset_Simplebim - Assembly Level: Leaf
AVINOR - 08_Status: S4; 07_Fase: F90; 06_Omrade: TI; 05_ID-nummer: +TI=241.025; 03_Ansvar: 72717; 02_Prosjekt: T20100; 01_Lufthavnkode: ENGM
ePset_LocationTool - Splitting: ORIGINAL

# IfcBuildingElementProxy: Model Text:Generisk skilting butikkfronter - 225mm Arial (2)
In: Nivå F
Pset_QuantityTakeOff - Reference: Generisk skilting butikkfronter - 225mm Arial; sets with these values: 2
AVINOR - 08_Status: S4; 06_Omrade: TI; 02_Prosjekt: T20100; 07_Fase: F50; 03_Ansvar: OSL; 01_Lufthavnkode: ENGM
ePset_Simplebim - Assembly Level: Leaf
ePset_SimplebimBasicQuantities - Volume, net (Simplebim): 0.00309399 m3
ePset_LocationTool - Splitting: ORIGINAL
Name (Model Text:Generisk skilting butikkfronter - 225mm Arial:...) | Length (Simplebim) (mm) | Area, largest surface, net (Simplebim) (m2) | Thickness (Simplebim) (mm) | Height (Simplebim) (mm)
68560719 | 533.83 | 0.0245278 | 31.3492 | 1320.97
68562826 | 483.791 | 0.024532 | 30.6061 | 1320.42

# IfcColumn: A241 - GRID-oppheng:A241 - GRID-oppheng - ø10 mm (30)
In: Nivå G - 2,0m
Type - PredefinedType: COLUMN; Material: _NSW Stål
Type - Pset_ColumnCommon - LoadBearing: yes
ePset_SimplebimBasicQuantities - Volume, net (Simplebim): 0.0000180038 m3; Area, sides, net (Simplebim): 0.0180724 m2; Width (Simplebim): 8 mm; Depth (Simplebim): 8 mm; Height (Simplebim): 480 mm; Weight, as steel (Simplebim): 0.14133 kg
AVINOR - 08_Status: S4; 07_Fase: F90; 05_ID-nummer: +TI=255.002; 06_Omrade: TI; 03_Ansvar: 72717; 02_Prosjekt: T20100; 01_Lufthavnkode: ENGM
ePset_Simplebim - Assembly Level: Leaf
ePset_LocationTool - Splitting: RESULT
Pset_ReinforcementBarPitchOfColumn - Reference: A241 - GRID-oppheng - ø10 mm; sets with these values: 2
Pset_ColumnCommon - IsExternal: no; Reference: A241 - GRID-oppheng - ø10 mm
Name (A241 - GRID-oppheng:A241 - GRID-oppheng - ø10 mm:...)
67258958
67258956
67258952
67258950
67258936
67258934
67258893
67258916
67258891
67258914
67258930
67258928
67258887
67258910
67258885
67258908
67258948
67258954
67258926
67258883
67258906
67258932
67258889
67258912
67258865
67258847
67258622
67258606
67258194
67258808

# IfcColumn: B222 - HUP:B222 - HUP - 200 x 100 x 8 (9)
In: Nivå F
Type - PredefinedType: COLUMN; Material: _NSW Stål
Type - Pset_ColumnCommon - LoadBearing: yes
ePset_SimplebimBasicQuantities - Weight, as steel (Simplebim): 217.652 kg; Height (Simplebim): 3065 mm; Width (Simplebim): 100 mm; Depth (Simplebim): 200 mm
Pset_ColumnCommon - Reference: B222 - HUP - 200 x 100 x 8; IsExternal: no
Pset_ReinforcementBarPitchOfColumn - Reference: B222 - HUP - 200 x 100 x 8; sets with these values: 2
AVINOR - 08_Status: S4; 07_Fase: F90; 06_Omrade: TI; 03_Ansvar: 72717; 02_Prosjekt: T20100; 01_Lufthavnkode: ENGM
ePset_Simplebim - Assembly Level: Leaf
ePset_LocationTool - Splitting: ORIGINAL
Name (B222 - HUP:B222 - HUP - 200 x 100 x 8:...) | Volume, net (Simplebim) (m3) | Area, sides, net (Simplebim) (m2)
54338458 | 0.0277263 | 6.90027
54615719 | 0.0277263 | 6.90027
54615862 | 0.0277263 | 6.90027
54615976 | 0.0277263 | 6.90027
54616265 | 0.0277263 | 6.90027
54616328 | 0.0277263 | 6.90027
54616422 | 0.0277264 | 6.90026
54616426 | 0.0277264 | 6.90026
54616432 | 0.0277264 | 6.90026

# IfcColumn: D1000 (2)
In: F
Description: D1000; Material: CONCRETE/C55/67
ePset_LocationTool - Splitting: ORIGINAL
AVINOR - 08_Status: S4; 07_Fase: F90; 06_Omrade: TI; 05_ID-nummer: +TI=222.003; 04_Kontrakt: 72241; 02_Prosjekt: T20100; 03_Ansvar: 72101; 01_Lufthavnkode: ENGM
ePset_SimplebimBasicQuantities - Volume, net (Simplebim): 3.42384 m3; Area, sides, net (Simplebim): 13.7204 m2; Weight, as steel (Simplebim): 26877.2 kg; Width (Simplebim): 1000 mm; Depth (Simplebim): 1000 mm; Height (Simplebim): 4370 mm
Pset_ColumnCommon - Reference: Concrete-17158(?); LoadBearing: no
ePset_Simplebim - Assembly Level: Leaf
Tekla Quantity - AREA_GROSS: 15.2874 m2; AREA_NET: 15.2874 m2; Heigth: 1000 mm; Width: 1000 mm; Length: 4370 mm; WEIGTH_NET: 8217.23 kg; WEIGTH_GROSS: 8217.23 kg; VOLUME_NET: 3.42384 m3; VOLUME_GROSS: 3.42384 m3
Tekla Common - Profile: D1000; Part mark: Concrete-17158(?); Class: 220; Bottom elevation: +210.830; Name: PLASSTØPTSØYLE; Top elevation: +215.200; Grade: C55/67
Name | Assembly mark
PLASSTØPTSØYLE | PLS-1005(?)
PLASSTØPTSØYLE | PLS-1004(?)

# IfcColumn: PL10*100 (2)
In: F
Description: PL10*100; Material: STEEL/S355
ePset_SimplebimBasicQuantities - Height (Simplebim): 185 mm; Width (Simplebim): 10 mm; Depth (Simplebim): 100 mm
Pset_ColumnCommon - LoadBearing: no; Reference: DSS-0(?)
ePset_Simplebim - Assembly Level: Leaf
AVINOR - 08_Status: S4; 07_Fase: F90; 06_Omrade: TI; 05_ID-nummer: +TI=221.038; 04_Kontrakt: 72717; 02_Prosjekt: T20100; 03_Ansvar: 72101; 01_Lufthavnkode: ENGM
ePset_LocationTool - Splitting: ORIGINAL
Tekla Common - Assembly mark: SD-786(?); Grade: S355; Class: 320; Name: STÅLSØYLE; Part mark: DSS-0(?); Profile: PL10*100
Tekla Quantity - AREA_GROSS: 0.04269 m2; Length: 185 mm; VOLUME_NET: 0.00017 m3; VOLUME_GROSS: 0.00017 m3; Width: 10 mm; Heigth: 100 mm; WEIGTH_GROSS: 1.45225 kg
Name | Volume, net (Simplebim) (m3) | Area, sides, net (Simplebim) (m2) | Weight, as steel (Simplebim) (kg) = WEIGTH_NET (kg) | Top elevation | Bottom elevation | AREA_NET (m2)
STÅLSØYLE | 0.000182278 | 0.040246 | 1.43088 | +213.247 | +213.043 | 0.04202
STÅLSØYLE | 0.000185 | 0.0407 | 1.45225 | +211.102 | +210.899 | 0.0427

# IfcColumn: PL10*120 (4)
In: F
Description: PL10*120; Material: STEEL/S355
Pset_ColumnCommon - Reference: DSS-2756(?); LoadBearing: no
Tekla Quantity - VOLUME_GROSS: 0.00031 m3; VOLUME_NET: 0.00031 m3; AREA_GROSS: 0.07 m2; Width: 10 mm; Heigth: 120 mm; Length: 260 mm; AREA_NET: 0.06999 m2; WEIGTH_GROSS: 2.4492 kg; WEIGTH_NET: 2.4492 kg
Tekla Common - Grade: S355; Class: 320; Bottom elevation: +210.870; Top elevation: +210.880; Part mark: DSS-2756(?); Name: STÅLSØYLE; Assembly mark: SS-8144(?); Profile: PL10*120
ePset_Simplebim - Assembly Level: Leaf
AVINOR - 04_Kontrakt: 72253; 05_ID-nummer: +TI=221.025; 08_Status: S4; 07_Fase: F90; 06_Omrade: TI; 02_Prosjekt: T20100; 03_Ansvar: 72101; 01_Lufthavnkode: ENGM
ePset_LocationTool - Splitting: ORIGINAL
ePset_SimplebimBasicQuantities - Volume, net (Simplebim): 0.000312 m3; Width (Simplebim): 10 mm; Depth (Simplebim): 120 mm; Height (Simplebim): 260 mm; Area, sides, net (Simplebim): 0.0076 m2; Weight, as steel (Simplebim): 2.4492 kg

# IfcColumn: PL10*150 (4)
In: F
Description: PL10*150; Material: STEEL/S355J0
Pset_ColumnCommon - LoadBearing: no; Reference: DSS-0(?)
ePset_Simplebim - Assembly Level: Leaf
AVINOR - 08_Status: S4; 07_Fase: F90; 06_Omrade: TI; 05_ID-nummer: +TI=221.038; 04_Kontrakt: 72717; 02_Prosjekt: T20100; 03_Ansvar: 72101; 01_Lufthavnkode: ENGM
Tekla Quantity - Width: 10 mm; Heigth: 150 mm
ePset_LocationTool - Splitting: ORIGINAL
ePset_SimplebimBasicQuantities - Width (Simplebim): 10 mm; Depth (Simplebim): 150 mm
Tekla Common - Top elevation: +213.578; Bottom elevation: +213.568; Class: 320; Name: STÅLSØYLE; Grade: S355J0; Part mark: DSS-0(?); Profile: PL10*150
Name | VOLUME_NET (m3) = VOLUME_GROSS (m3) | AREA_NET (m2) | AREA_GROSS (m2) | Length (mm) = Height (Simplebim) (mm) | WEIGTH_NET (kg) = WEIGTH_GROSS (kg) = Weight, as steel (Simplebim) (kg) | Area, sides, net (Simplebim) (m2) | Volume, net (Simplebim) (m3) | Assembly mark
STÅLSØYLE | 0.00022 | 0.051 | 0.051 | 150 | 1.76625 | 0.006 | 0.000225 | SS-9536(?)
2 x STÅLSØYLE | 0.00022 | 0.051 | 0.051 | 150 | 1.76625 | 0.006 | 0.000225 | SS-0(?)
STÅLSØYLE | 0.00031 | 0.06701 | 0.067 | 200 | 2.355 | 0.007 | 0.0003 | SS-9536(?)

# IfcColumn: PL10*180, STÅLSØYLE
In: F
Description: PL10*180; Material: STEEL/S355J0
Tekla Common - Class: 320; Name: STÅLSØYLE; Top elevation: +213.693; Bottom elevation: +213.513; Assembly mark: SB-11789(?); Grade: S355J0; Part mark: DSS-0(?); Profile: PL10*180
Pset_ColumnCommon - LoadBearing: no; Reference: DSS-0(?)
ePset_Simplebim - Assembly Level: Leaf
AVINOR - 08_Status: S4; 07_Fase: F90; 06_Omrade: TI; 05_ID-nummer: +TI=221.038; 04_Kontrakt: 72717; 02_Prosjekt: T20100; 03_Ansvar: 72101; 01_Lufthavnkode: ENGM
ePset_SimplebimBasicQuantities - Area, sides, net (Simplebim): 0.0503975 m2; Weight, as steel (Simplebim): 1.8368 kg; Height (Simplebim): 180 mm; Width (Simplebim): 10 mm; Depth (Simplebim): 129.993 mm; Volume, net (Simplebim): 0.000233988 m3
Tekla Quantity - VOLUME_NET: 0.00022 m3; VOLUME_GROSS: 0.00022 m3; AREA_NET: 0.053 m2; AREA_GROSS: 0.053 m2; Length: 129.996 mm; Width: 10 mm; Heigth: 180 mm; WEIGTH_NET: 1.83684 kg; WEIGTH_GROSS: 1.83684 kg
ePset_LocationTool - Splitting: ORIGINAL

# IfcColumn: PL10*204, STÅLSØYLE
In: F
Description: PL10*204; Material: STEEL/S355
Tekla Common - Grade: S355; Bottom elevation: +213.127; Assembly mark: SS-0(?); Class: 320; Name: STÅLSØYLE; Part mark: DSS-0(?); Profile: PL10*204; Top elevation: +213.290
Pset_ColumnCommon - LoadBearing: no; Reference: DSS-0(?)
ePset_Simplebim - Assembly Level: Leaf
AVINOR - 08_Status: S4; 07_Fase: F90; 06_Omrade: TI; 05_ID-nummer: +TI=221.038; 04_Kontrakt: 72717; 02_Prosjekt: T20100; 03_Ansvar: 72101; 01_Lufthavnkode: ENGM
ePset_LocationTool - Splitting: ORIGINAL
Tekla Quantity - AREA_GROSS: 0.03321 m2; VOLUME_NET: 0.00022 m3; VOLUME_GROSS: 0.00022 m3; WEIGTH_GROSS: 2.60703 kg; AREA_NET: 0.05229 m2; Width: 10 mm; Length: 163.069 mm; Heigth: 203.66 mm; WEIGTH_NET: 1.80845 kg
ePset_SimplebimBasicQuantities - Weight, as steel (Simplebim): 1.80845 kg; Depth (Simplebim): 163.07 mm; Area, sides, net (Simplebim): 0.0491084 m2; Width (Simplebim): 10 mm; Height (Simplebim): 203.661 mm; Volume, net (Simplebim): 0.000230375 m3

# IfcColumn: PL10*216, STÅLSØYLE
In: F
Description: PL10*216; Material: STEEL/S355
ePset_SimplebimBasicQuantities - Depth (Simplebim): 173.303 mm; Weight, as steel (Simplebim): 2.45479 kg; Volume, net (Simplebim): 0.000312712 m3; Width (Simplebim): 10 mm; Area, sides, net (Simplebim): 0.0655279 m2; Height (Simplebim): 215.644 mm
Pset_ColumnCommon - Reference: DSS-5852(?); LoadBearing: no
ePset_Simplebim - Assembly Level: Leaf
AVINOR - 08_Status: S4; 07_Fase: F90; 06_Omrade: TI; 05_ID-nummer: +TI=221.038; 04_Kontrakt: 72717; 02_Prosjekt: T20100; 03_Ansvar: 72101; 01_Lufthavnkode: ENGM
Tekla Common - Grade: S355; Part mark: DSS-5852(?); Assembly mark: SS-0(?); Class: 320; Name: STÅLSØYLE; Bottom elevation: +210.845; Profile: PL10*216; Top elevation: +211.018
Tekla Quantity - WEIGTH_NET: 2.45479 kg; Length: 173.303 mm; VOLUME_GROSS: 0.00031 m3; VOLUME_NET: 0.00031 m3; AREA_GROSS: 0.03737 m2; AREA_NET: 0.06943 m2; WEIGTH_GROSS: 2.93369 kg; Width: 10 mm; Heigth: 215.644 mm
ePset_LocationTool - Splitting: ORIGINAL

# IfcColumn: PL15*170, STÅLSØYLE
In: F
Description: PL15*170; Material: STEEL/S355
ePset_Simplebim - Assembly Level: Leaf
ePset_SimplebimBasicQuantities - Depth (Simplebim): 170.003 mm; Weight, as steel (Simplebim): 7.46504 kg; Area, sides, net (Simplebim): 0.0261762 m2; Width (Simplebim): 15 mm; Volume, net (Simplebim): 0.000950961 m3; Height (Simplebim): 702.504 mm
AVINOR - 08_Status: S4; 07_Fase: F90; 06_Omrade: TI; 05_ID-nummer: +TI=221.038; 04_Kontrakt: 72717; 02_Prosjekt: T20100; 03_Ansvar: 72101; 01_Lufthavnkode: ENGM
ePset_LocationTool - Splitting: ORIGINAL
Tekla Common - Profile: PL15*170; Grade: S355; Assembly mark: SS-0(?); Class: 320; Bottom elevation: +210.880; Name: STÅLSØYLE; Part mark: DSS-5408(?); Top elevation: +210.895
Tekla Quantity - WEIGTH_GROSS: 14.0625 kg; AREA_GROSS: 0.11943 m2; Length: 702.505 mm; Heigth: 170.001 mm; WEIGTH_NET: 7.46504 kg; Width: 15 mm; VOLUME_NET: 0.00095 m3; VOLUME_GROSS: 0.00095 m3; AREA_NET: 0.15297 m2
Pset_ColumnCommon - Reference: DSS-5408(?); LoadBearing: no

# IfcColumn: PL15*185, STÅLSØYLE
In: F
Description: PL15*185; Material: STEEL/S355
Tekla Common - Grade: S355; Profile: PL15*185; Assembly mark: SS-0(?); Class: 320; Bottom elevation: +210.880; Name: STÅLSØYLE; Part mark: DSS-5408(?); Top elevation: +210.895
ePset_LocationTool - Splitting: ORIGINAL
ePset_SimplebimBasicQuantities - Height (Simplebim): 220.42 mm; Depth (Simplebim): 209.053 mm; Width (Simplebim): 15 mm; Area, sides, net (Simplebim): 0.0115038 m2; Volume, net (Simplebim): 0.000364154 m3; Weight, as steel (Simplebim): 2.85861 kg
ePset_Simplebim - Assembly Level: Leaf
AVINOR - 08_Status: S4; 07_Fase: F90; 06_Omrade: TI; 05_ID-nummer: +TI=221.038; 04_Kontrakt: 72717; 02_Prosjekt: T20100; 03_Ansvar: 72101; 01_Lufthavnkode: ENGM
Tekla Quantity - WEIGTH_NET: 2.85861 kg; VOLUME_NET: 0.00035 m3; VOLUME_GROSS: 0.00035 m3; Heigth: 184.775 mm; WEIGTH_GROSS: 5.20077 kg; AREA_NET: 0.06006 m2; Width: 15 mm; Length: 239.037 mm; AREA_GROSS: 0.04417 m2
Pset_ColumnCommon - Reference: DSS-5408(?); LoadBearing: no

# IfcColumn: PL15*280, STÅLSØYLE
In: F
Description: PL15*280; Material: STEEL/S355
Tekla Quantity - AREA_GROSS: 0.0784 m2; WEIGTH_GROSS: 9.23159 kg; Length: 280.001 mm; Heigth: 279.999 mm; Width: 15 mm; WEIGTH_NET: 9.23156 kg; VOLUME_NET: 0.00118 m3; VOLUME_GROSS: 0.00118 m3; AREA_NET: 0.1736 m2
ePset_Simplebim - Assembly Level: Leaf
AVINOR - 08_Status: S4; 07_Fase: F90; 06_Omrade: TI; 05_ID-nummer: +TI=221.038; 04_Kontrakt: 72717; 02_Prosjekt: T20100; 03_Ansvar: 72101; 01_Lufthavnkode: ENGM
ePset_SimplebimBasicQuantities - Volume, net (Simplebim): 0.001176 m3; Height (Simplebim): 280.001 mm; Depth (Simplebim): 279.999 mm; Weight, as steel (Simplebim): 9.23156 kg; Area, sides, net (Simplebim): 0.0168 m2; Width (Simplebim): 15 mm
Pset_ColumnCommon - Reference: DSS-5408(?); LoadBearing: no
Tekla Common - Grade: S355; Assembly mark: SS-0(?); Class: 320; Bottom elevation: +210.830; Profile: PL15*280; Name: STÅLSØYLE; Part mark: DSS-5408(?); Top elevation: +210.845
ePset_LocationTool - Splitting: ORIGINAL

# IfcColumn: PL15*320, STÅLSØYLE
In: F
Description: PL15*320; Material: STEEL/S355
ePset_SimplebimBasicQuantities - Volume, net (Simplebim): 0.00149099 m3; Area, sides, net (Simplebim): 0.0186 m2; Height (Simplebim): 320.001 mm; Depth (Simplebim): 319.999 mm; Weight, as steel (Simplebim): 11.7043 kg; Width (Simplebim): 15 mm
ePset_Simplebim - Assembly Level: Leaf
AVINOR - 08_Status: S4; 07_Fase: F90; 06_Omrade: TI; 05_ID-nummer: +TI=221.038; 04_Kontrakt: 72717; 02_Prosjekt: T20100; 03_Ansvar: 72101; 01_Lufthavnkode: ENGM
ePset_LocationTool - Splitting: ORIGINAL
Tekla Common - Grade: S355; Profile: PL15*320; Class: 320; Bottom elevation: +210.830; Name: STÅLSØYLE; Part mark: DSS-5408(?); Top elevation: +210.845; Assembly mark: SS-9536(?)
Tekla Quantity - VOLUME_GROSS: 0.0015 m3; VOLUME_NET: 0.0015 m3; AREA_GROSS: 0.1024 m2; Length: 320.001 mm; Heigth: 319.999 mm; WEIGTH_NET: 11.7043 kg; Width: 15 mm; AREA_NET: 0.2174 m2; WEIGTH_GROSS: 12.0576 kg
Pset_ColumnCommon - Reference: DSS-5408(?); LoadBearing: no

# IfcColumn: PL15*80 (2)
In: F
Description: PL15*80; Material: STEEL/S355
ePset_Simplebim - Assembly Level: Leaf
AVINOR - 08_Status: S4; 07_Fase: F90; 06_Omrade: TI; 05_ID-nummer: +TI=221.038; 04_Kontrakt: 72717; 02_Prosjekt: T20100; 03_Ansvar: 72101; 01_Lufthavnkode: ENGM
ePset_LocationTool - Splitting: ORIGINAL
Tekla Quantity - Heigth: 79.9989 mm; Width: 15 mm
Tekla Common - Grade: S355; Class: 320; Bottom elevation: +210.880; Profile: PL15*80; Name: STÅLSØYLE; Part mark: DSS-5408(?); Top elevation: +210.895
Pset_ColumnCommon - Reference: DSS-5408(?); LoadBearing: no
ePset_SimplebimBasicQuantities - Depth (Simplebim): 79.9989 mm; Width (Simplebim): 15 mm
Name | WEIGTH_NET (kg) = Weight, as steel (Simplebim) (kg) | WEIGTH_GROSS (kg) | VOLUME_NET (m3) = VOLUME_GROSS (m3) | Length (mm) = Height (Simplebim) (mm) | AREA_GROSS (m2) | AREA_NET (m2) | Assembly mark | Volume, net (Simplebim) (m3) | Area, sides, net (Simplebim) (m2)
STÅLSØYLE | 7.8185 | 7.8185 | 0.001 | 830.001 | 0.0664 | 0.1601 | SS-0(?) | 0.000995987 | 0.0273
STÅLSØYLE | 2.63756 | 2.63757 | 0.00034 | 280.001 | 0.0224 | 0.0556 | SS-9536(?) | 0.000335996 | 0.0108

# IfcColumn: PL15*90, STÅLSØYLE
In: F
Description: PL15*90; Material: STEEL/S355
Tekla Quantity - AREA_NET: 0.177 m2; VOLUME_GROSS: 0.00112 m3; VOLUME_NET: 0.00112 m3; WEIGTH_NET: 8.79582 kg; Length: 830.001 mm; AREA_GROSS: 0.0747 m2; Heigth: 89.9989 mm; Width: 15 mm; WEIGTH_GROSS: 8.79583 kg
ePset_SimplebimBasicQuantities - Weight, as steel (Simplebim): 8.79582 kg; Height (Simplebim): 830.001 mm; Area, sides, net (Simplebim): 0.0276 m2; Depth (Simplebim): 89.9989 mm; Width (Simplebim): 15 mm; Volume, net (Simplebim): 0.00112049 m3
ePset_LocationTool - Splitting: ORIGINAL
ePset_Simplebim - Assembly Level: Leaf
Tekla Common - Grade: S355; Assembly mark: SS-0(?); Class: 320; Bottom elevation: +210.880; Name: STÅLSØYLE; Part mark: DSS-5408(?); Top elevation: +210.895; Profile: PL15*90
AVINOR - 08_Status: S4; 07_Fase: F90; 06_Omrade: TI; 05_ID-nummer: +TI=221.038; 04_Kontrakt: 72717; 02_Prosjekt: T20100; 03_Ansvar: 72101; 01_Lufthavnkode: ENGM
Pset_ColumnCommon - Reference: DSS-5408(?); LoadBearing: no

# IfcColumn: PL25*260 (10)
In: F
Description: PL25*260; Material: STEEL/S355
Tekla Common - Grade: S355; Class: 320; Profile: PL25*260; Name: STÅLSØYLE
ePset_SimplebimBasicQuantities - Height (Simplebim): 450 mm; Weight, as steel (Simplebim): 22.9612 kg; Width (Simplebim): 25 mm; Depth (Simplebim): 260 mm; Volume, net (Simplebim): 0.002925 m3; Area, sides, net (Simplebim): 0.0355 m2
Tekla Quantity - AREA_GROSS: 0.2695 m2; AREA_NET: 0.2695 m2; WEIGTH_GROSS: 22.9612 kg; WEIGTH_NET: 22.9612 kg; Width: 25 mm; Heigth: 260 mm; Length: 450 mm
ePset_Simplebim - Assembly Level: Leaf
Pset_ColumnCommon - LoadBearing: no
ePset_LocationTool - Splitting: ORIGINAL
AVINOR - 04_Kontrakt: 72253; 05_ID-nummer: +TI=221.025; 08_Status: S4; 07_Fase: F90; 06_Omrade: TI; 02_Prosjekt: T20100; 03_Ansvar: 72101; 01_Lufthavnkode: ENGM
Name | Part mark = Reference | Bottom elevation | Top elevation | Assembly mark | VOLUME_GROSS (m3) = VOLUME_NET (m3)
3 x STÅLSØYLE | DSS-6140(?) | +210.830 | +210.855 | 263(?) | 0.00292
2 x STÅLSØYLE | DSS-6139(?) | +210.830 | +210.855 | 262(?) | 0.00292
2 x STÅLSØYLE | DSS-6183(?) | +210.830 | +210.855 | SS-7605(?) | 0.00293
3 x STÅLSØYLE | DSS-6137(?) | +210.680 | +210.705 | SS-9159(?) | 0.00293

# IfcColumn: PL25*320, STÅLSØYLE
In: F
Description: PL25*320; Material: STEEL/S355
ePset_LocationTool - Splitting: ORIGINAL
ePset_Simplebim - Assembly Level: Leaf
AVINOR - 04_Kontrakt: 72253; 05_ID-nummer: +TI=221.025; 08_Status: S4; 07_Fase: F90; 06_Omrade: TI; 02_Prosjekt: T20100; 03_Ansvar: 72101; 01_Lufthavnkode: ENGM
Tekla Quantity - WEIGTH_NET: 28.26 kg; WEIGTH_GROSS: 28.26 kg; Width: 25 mm; Heigth: 320 mm; Length: 450 mm; VOLUME_GROSS: 0.0036 m3; VOLUME_NET: 0.0036 m3; AREA_NET: 0.3265 m2; AREA_GROSS: 0.3265 m2
Tekla Common - Grade: S355; Profile: PL25*320; Class: 320; Bottom elevation: +210.830; Name: STÅLSØYLE; Top elevation: +210.855; Assembly mark: 264(?); Part mark: DSS-6141(?)
Pset_ColumnCommon - LoadBearing: no; Reference: DSS-6141(?)
ePset_SimplebimBasicQuantities - Area, sides, net (Simplebim): 0.0385 m2; Weight, as steel (Simplebim): 28.26 kg; Width (Simplebim): 25 mm; Depth (Simplebim): 320 mm; Height (Simplebim): 450 mm; Volume, net (Simplebim): 0.0036 m3

# IfcColumn: PL25*500, STÅLSØYLE
In: F
Description: PL25*500; Material: STEEL/S355
Tekla Quantity - VOLUME_GROSS: 0.00437 m3; VOLUME_NET: 0.00437 m3; Width: 25 mm; WEIGTH_NET: 34.3438 kg; WEIGTH_GROSS: 34.3438 kg; Length: 350 mm; Heigth: 500 mm; AREA_GROSS: 0.3925 m2; AREA_NET: 0.3925 m2
ePset_Simplebim - Assembly Level: Leaf
ePset_LocationTool - Splitting: ORIGINAL
ePset_SimplebimBasicQuantities - Volume, net (Simplebim): 0.004375 m3; Width (Simplebim): 25 mm; Weight, as steel (Simplebim): 34.3438 kg; Depth (Simplebim): 350 mm; Height (Simplebim): 500 mm; Area, sides, net (Simplebim): 0.0425 m2
AVINOR - 04_Kontrakt: 72253; 05_ID-nummer: +TI=221.025; 08_Status: S4; 07_Fase: F90; 06_Omrade: TI; 02_Prosjekt: T20100; 03_Ansvar: 72101; 01_Lufthavnkode: ENGM
Tekla Common - Grade: S355; Part mark: DSS-72(?); Class: 320; Name: STÅLSØYLE; Assembly mark: SS-8144(?); Bottom elevation: +210.680; Profile: PL25*500; Top elevation: +210.705
Pset_ColumnCommon - Reference: DSS-72(?); LoadBearing: no

# IfcColumn: PL5*31 (4)
In: F
Description: PL5*31; Material: STEEL/S355
Tekla Quantity - AREA_NET: 0.00549 m2; VOLUME_GROSS: 0.00001 m3; VOLUME_NET: 0.00001 m3; WEIGTH_NET: 0.08761 kg; WEIGTH_GROSS: 0.08761 kg; Length: 72 mm; AREA_GROSS: 0.00223 m2; Width: 5 mm; Heigth: 31 mm
Pset_ColumnCommon - LoadBearing: no; Reference: DSS-0(?)
ePset_SimplebimBasicQuantities - Volume, net (Simplebim): 0.00001116 m3; Weight, as steel (Simplebim): 0.087606 kg; Area, sides, net (Simplebim): 0.00103 m2; Width (Simplebim): 5 mm; Depth (Simplebim): 31 mm; Height (Simplebim): 72 mm
ePset_LocationTool - Splitting: ORIGINAL
ePset_Simplebim - Assembly Level: Leaf
AVINOR - 08_Status: S4; 07_Fase: F90; 06_Omrade: TI; 05_ID-nummer: +TI=221.038; 04_Kontrakt: 72717; 02_Prosjekt: T20100; 03_Ansvar: 72101; 01_Lufthavnkode: ENGM
Tekla Common - Assembly mark: SD-786(?); Grade: S355; Class: 320; Name: STÅLSØYLE; Profile: PL5*31; Part mark: DSS-0(?)
Name | Bottom elevation | Top elevation
2 x STÅLSØYLE | +213.126 | +213.179
2 x STÅLSØYLE | +210.966 | +211.020

# IfcColumn: PL5*72 (2)
In: F
Description: PL5*72; Material: STEEL/S355J0
Pset_ColumnCommon - LoadBearing: no; Reference: DSS-0(?)
Tekla Common - Assembly mark: SS-0(?); Class: 320; Profile: PL5*72; Name: STÅLSØYLE; Grade: S355J0; Part mark: DSS-0(?)
ePset_SimplebimBasicQuantities - Weight, as steel (Simplebim): 0.203472 kg; Volume, net (Simplebim): 0.00002592 m3; Area, sides, net (Simplebim): 0.00144 m2; Width (Simplebim): 5 mm; Height (Simplebim): 72 mm; Depth (Simplebim): 72 mm
ePset_Simplebim - Assembly Level: Leaf
AVINOR - 08_Status: S4; 07_Fase: F90; 06_Omrade: TI; 05_ID-nummer: +TI=221.038; 04_Kontrakt: 72717; 02_Prosjekt: T20100; 03_Ansvar: 72101; 01_Lufthavnkode: ENGM
ePset_LocationTool - Splitting: ORIGINAL
Tekla Quantity - WEIGTH_NET: 0.20347 kg; WEIGTH_GROSS: 0.20347 kg; Width: 5 mm; Heigth: 72 mm; Length: 72 mm; AREA_NET: 0.01181 m2; AREA_GROSS: 0.01181 m2; VOLUME_NET: 0.00003 m3; VOLUME_GROSS: 0.00003 m3
Name | Bottom elevation | Top elevation
STÅLSØYLE | +213.595 | +213.600
STÅLSØYLE | +213.573 | +213.578

# IfcColumn: PL60*10 (6)
In: F
Description: PL60*10; Material: STEEL/S355
ePset_SimplebimBasicQuantities - Area, sides, net (Simplebim): 0.0938 m2; Weight, as steel (Simplebim): 3.1557 kg; Volume, net (Simplebim): 0.000402 m3; Width (Simplebim): 10 mm; Depth (Simplebim): 60 mm; Height (Simplebim): 670 mm
Tekla Quantity - AREA_NET: 0.095 m2; AREA_GROSS: 0.095 m2; VOLUME_NET: 0.0004 m3; WEIGTH_GROSS: 3.1557 kg; WEIGTH_NET: 3.1557 kg; VOLUME_GROSS: 0.00039 m3; Width: 10 mm; Heigth: 60 mm; Length: 670 mm
ePset_Simplebim - Assembly Level: Leaf
Pset_ColumnCommon - Reference: DSS-5926(?); LoadBearing: no
Tekla Common - Part mark: DSS-5926(?); Grade: S355; Profile: PL60*10; Class: 320; Top elevation: +211.575; Name: STÅLSØYLE; Bottom elevation: +210.905; Assembly mark: SS-9056(?)
ePset_LocationTool - Splitting: ORIGINAL
AVINOR - 04_Kontrakt: 72253; 05_ID-nummer: +TI=221.025; 08_Status: S4; 07_Fase: F90; 06_Omrade: TI; 02_Prosjekt: T20100; 03_Ansvar: 72101; 01_Lufthavnkode: ENGM

# IfcColumn: PL8*105 (2)
In: F
Description: PL8*105; Material: STEEL/S355J0
Tekla Common - Assembly mark: SS-0(?); Class: 320; Name: STÅLSØYLE; Profile: PL8*105; Grade: S355J0; Part mark: DSS-0(?)
Pset_ColumnCommon - LoadBearing: no; Reference: DSS-0(?)
Tekla Quantity - AREA_NET: 0.04236 m2; AREA_GROSS: 0.0189 m2; WEIGTH_GROSS: 1.18692 kg; WEIGTH_NET: 1.18692 kg; VOLUME_NET: 0.00015 m3; VOLUME_GROSS: 0.00015 m3; Length: 180 mm; Width: 8 mm; Heigth: 105 mm
ePset_Simplebim - Assembly Level: Leaf
AVINOR - 08_Status: S4; 07_Fase: F90; 06_Omrade: TI; 05_ID-nummer: +TI=221.038; 04_Kontrakt: 72717; 02_Prosjekt: T20100; 03_Ansvar: 72101; 01_Lufthavnkode: ENGM
ePset_SimplebimBasicQuantities - Weight, as steel (Simplebim): 1.18692 kg; Height (Simplebim): 180 mm; Area, sides, net (Simplebim): 0.03948 m2; Width (Simplebim): 8 mm; Depth (Simplebim): 105 mm; Volume, net (Simplebim): 0.0001512 m3
ePset_LocationTool - Splitting: ORIGINAL
Name | Top elevation | Bottom elevation
STÅLSØYLE | +213.560 | +213.455
STÅLSØYLE | +213.420 | +213.315

# IfcColumn: RHS100*10, STÅLSØYLE
In: F
Description: RHS100*10; Material: STEEL/S355
ePset_LocationTool - Splitting: ORIGINAL
ePset_SimplebimBasicQuantities - Weight, as steel (Simplebim): 87.3234 kg; Height (Simplebim): 3090 mm; Width (Simplebim): 100 mm; Depth (Simplebim): 100 mm; Volume, net (Simplebim): 0.011124 m3; Area, sides, net (Simplebim): 2.2248 m2
ePset_Simplebim - Assembly Level: Leaf
Tekla Quantity - WEIGTH_GROSS: 86.1106 kg; WEIGTH_NET: 87.3234 kg; AREA_GROSS: 1.17111 m2; AREA_NET: 1.24 m2; Length: 3090 mm; VOLUME_NET: 0.01112 m3; Heigth: 100 mm; Width: 100 mm; VOLUME_GROSS: 0.01097 m3
AVINOR - 04_Kontrakt: 72253; 05_ID-nummer: +TI=221.025; 08_Status: S4; 07_Fase: F90; 06_Omrade: TI; 02_Prosjekt: T20100; 03_Ansvar: 72101; 01_Lufthavnkode: ENGM
Tekla Common - Grade: S355; Profile: RHS100*10; Class: 320; Top elevation: +213.795; Name: STÅLSØYLE; Assembly mark: SS-8144(?); Part mark: DSS-7678(?); Bottom elevation: +210.705
Pset_ColumnCommon - LoadBearing: no; Reference: DSS-7678(?)

# IfcColumn: RHS100*6.3 (5)
In: D
Description: RHS100*6.3; Material: STEEL/S355
Tekla Common - Grade: S355; Class: 320; Bottom elevation: +210.303; Name: STÅLSØYLE; Part mark: DSS-3652; Profile: RHS100*6.3; Top elevation: +210.453; Assembly mark: SB-7035
AVINOR - 08_Status: S4; 07_Fase: F40; 06_Omrade: TI; 05_ID-nummer: +TI=222.006; 03_Ansvar: 72242; 04_Kontrakt: 72242; 02_Prosjekt: T20100; 01_Lufthavnkode: ENGM
ePset_Simplebim - Assembly Level: Leaf
Pset_ColumnCommon - Reference: DSS-3652; LoadBearing: no
ePset_SimplebimBasicQuantities - Area, sides, net (Simplebim): 0.1128 m2; Volume, net (Simplebim): 0.0003384 m3; Weight, as steel (Simplebim): 2.65644 kg; Width (Simplebim): 100 mm; Depth (Simplebim): 100 mm; Height (Simplebim): 150 mm
Tekla Quantity - Length: 150 mm; AREA_GROSS: 0.0579 m2; VOLUME_NET: 0.00035 m3; VOLUME_GROSS: 0.00035 m3; AREA_NET: 0.06252 m2; WEIGTH_NET: 2.78037 kg; Heigth: 100 mm; Width: 100 mm; WEIGTH_GROSS: 2.75536 kg
ePset_LocationTool - Splitting: ORIGINAL

# IfcColumn: RHS160*80*8 (3)
In: F
Description: RHS160*80*8; Material: STEEL/S355
ePset_LocationTool - Splitting: ORIGINAL
ePset_Simplebim - Assembly Level: Leaf
Tekla Quantity - VOLUME_GROSS: 0.00311 m3; WEIGTH_NET: 24.2659 kg; AREA_NET: 0.41219 m2; VOLUME_NET: 0.00309 m3; Length: 875.001 mm; Width: 80 mm; Heigth: 160 mm; WEIGTH_GROSS: 24.3841 kg; AREA_GROSS: 0.40513 m2
ePset_SimplebimBasicQuantities - Volume, net (Simplebim): 0.0030912 m3; Weight, as steel (Simplebim): 24.2659 kg; Area, sides, net (Simplebim): 0.776001 m2; Height (Simplebim): 875.001 mm; Width (Simplebim): 80 mm; Depth (Simplebim): 160 mm
Pset_ColumnCommon - Reference: DSS-6939(?); LoadBearing: no
AVINOR - 04_Kontrakt: 72253; 05_ID-nummer: +TI=221.025; 08_Status: S4; 07_Fase: F90; 06_Omrade: TI; 02_Prosjekt: T20100; 03_Ansvar: 72101; 01_Lufthavnkode: ENGM
Tekla Common - Grade: S355; Class: 320; Top elevation: +211.580; Name: STÅLSØYLE; Part mark: DSS-6939(?); Assembly mark: SS-9159(?); Profile: RHS160*80*8; Bottom elevation: +210.705

# IfcColumn: RHS200*100*8 (11)
In: F
Description: RHS200*100*8; Material: STEEL/S355
Tekla Common - Grade: S355; Class: 320; Name: STÅLSØYLE; Profile: RHS200*100*8; Top elevation: +213.737
ePset_Simplebim - Assembly Level: Leaf
AVINOR - 04_Kontrakt: 72253; 05_ID-nummer: +TI=221.025; 08_Status: S4; 07_Fase: F90; 06_Omrade: TI; 02_Prosjekt: T20100; 03_Ansvar: 72101; 01_Lufthavnkode: ENGM
Tekla Quantity - Width: 100 mm; Heigth: 200 mm
ePset_SimplebimBasicQuantities - Width (Simplebim): 100 mm; Depth (Simplebim): 200 mm
Pset_ColumnCommon - LoadBearing: no
ePset_LocationTool - Splitting: ORIGINAL
Name | Part mark = Reference | Bottom elevation | Assembly mark | WEIGTH_NET (kg) = Weight, as steel (Simplebim) (kg) | AREA_GROSS (m2) | VOLUME_NET (m3) | Length (mm) = Height (Simplebim) (mm) | WEIGTH_GROSS (kg) | AREA_NET (m2) | VOLUME_GROSS (m3) | Volume, net (Simplebim) (m3) | Area, sides, net (Simplebim) (m2)
2 x STÅLSØYLE | DSS-7502(?) | +210.855 | SS-7605(?) | 102.124 | 1.68021 | 0.01302 | 2882 | 102.033 | 1.70099 | 0.01299 | 0.0130094 | 3.25681
2 x STÅLSØYLE | DSS-7489(?) | +210.900 | SS-9579(?) | 100.726 | 1.65397 | 0.01283 | 2837 | 100.44 | 1.6773 | 0.01279 | 0.0128313 | 3.21133
STÅLSØYLE | DSS-7489(?) | +210.900 | SS-7611(?) | 100.726 | 1.65397 | 0.01283 | 2837 | 100.44 | 1.6773 | 0.01279 | 0.0128313 | 3.21133
3 x STÅLSØYLE | DSS-7502(?) | +210.855 | SS-7612(?) | 102.124 | 1.68021 | 0.01302 | 2882 | 102.033 | 1.70099 | 0.01299 | 0.0130094 | 3.25681
3 x STÅLSØYLE | DSS-7502(?) | +210.855 | SS-9586(?) | 102.124 | 1.68021 | 0.01302 | 2882 | 102.033 | 1.70099 | 0.01299 | 0.0130094 | 3.25681

# IfcColumn: RHS50*5 (3)
In: F
Description: RHS50*5; Material: STEEL/S355
Tekla Quantity - VOLUME_GROSS: 0.00124 m3; Heigth: 50 mm; Width: 50 mm
ePset_Simplebim - Assembly Level: Leaf
Pset_ColumnCommon - Reference: DSS-7299(?); LoadBearing: no
AVINOR - 08_Status: S4; 07_Fase: F90; 06_Omrade: TI; 05_ID-nummer: +TI=221.038; 04_Kontrakt: 72717; 02_Prosjekt: T20100; 03_Ansvar: 72101; 01_Lufthavnkode: ENGM
ePset_LocationTool - Splitting: ORIGINAL
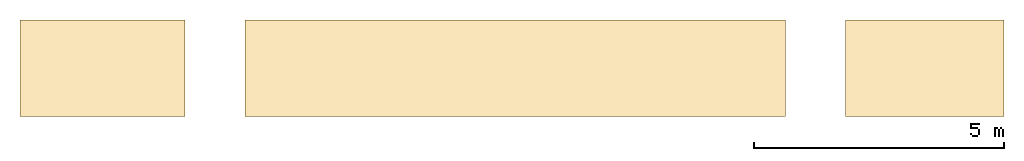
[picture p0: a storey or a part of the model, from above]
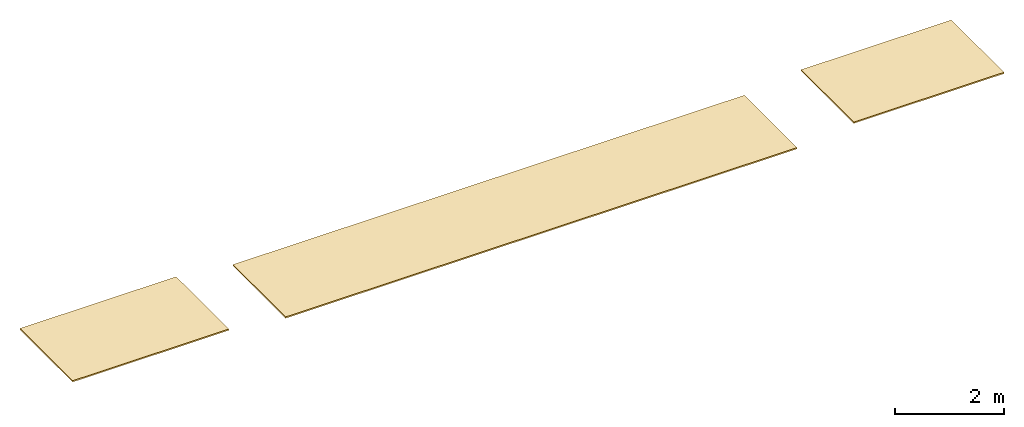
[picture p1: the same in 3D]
Properties of the parts of a building model (IFC2X3), part 2 of 3

# IfcColumn: RHS50*5 (3)
Tekla Common - Profile: RHS50*5; Grade: S355; Assembly mark: SS-0(?); Class: 320; Part mark: DSS-7299(?); Name: STÅLSØYLE
ePset_SimplebimBasicQuantities - Depth (Simplebim): 50 mm; Width (Simplebim): 50 mm
Name | AREA_NET (m2) | VOLUME_NET (m3) | WEIGTH_GROSS (kg) | Length (mm) = Height (Simplebim) (mm) | AREA_GROSS (m2) | WEIGTH_NET (kg) = Weight, as steel (Simplebim) (kg) | Bottom elevation | Top elevation | Volume, net (Simplebim) (m3) | Area, sides, net (Simplebim) (m2)
STÅLSØYLE | 0.27059 | 0.00121 | 9.64965 | 1384.3 | 0.26163 | 9.51269 | +211.757 | +212.586 | 0.00121181 | 0.245232
STÅLSØYLE | 0.27168 | 0.00122 | 9.68958 | 1390.02 | 0.26271 | 9.55095 | +212.585 | +213.423 | 0.00121668 | 0.246213
STÅLSØYLE | 0.27122 | 0.00121 | 9.6533 | 1384.82 | 0.26173 | 9.53499 | +210.915 | +211.743 | 0.00121465 | 0.245651

# IfcColumn: RHS80*6.3 (11)
In: F
Description: RHS80*6.3; Material: STEEL/S355
ePset_SimplebimBasicQuantities - Width (Simplebim): 80 mm; Depth (Simplebim): 80 mm
ePset_LocationTool - Splitting: ORIGINAL
ePset_Simplebim - Assembly Level: Leaf
Pset_ColumnCommon - LoadBearing: no
AVINOR - 08_Status: S4; 07_Fase: F90; 06_Omrade: TI; 02_Prosjekt: T20100; 03_Ansvar: 72101; 01_Lufthavnkode: ENGM
Tekla Quantity - Heigth: 80 mm; Width: 80 mm
Tekla Common - Grade: S355; Profile: RHS80*6.3; Class: 320; Name: STÅLSØYLE
Name | Volume, net (Simplebim) (m3) | Area, sides, net (Simplebim) (m2) | Weight, as steel (Simplebim) (kg) = WEIGTH_NET (kg) | Height (Simplebim) (mm) = Length (mm) | Reference = Part mark | 05_ID-nummer | 04_Kontrakt | AREA_GROSS (m2) | VOLUME_NET (m3) | AREA_NET (m2) | WEIGTH_GROSS (kg) | VOLUME_GROSS (m3) | Top elevation | Assembly mark | Bottom elevation
2 x STÅLSØYLE | 0.0049644 | 1.576 | 38.9706 | 2673 | DSS-7299(?) | +TI=221.038 | 72717 | 0.81794 | 0.00496 | 0.85738 | 38.6088 | 0.00492 | +213.568 | SS-0(?) | +210.895
STÅLSØYLE | 0.00505726 | 1.60548 | 39.6995 | 2723 | DSS-7299(?) | +TI=221.038 | 72717 | 0.83324 | 0.00505 | 0.87338 | 39.331 | 0.00501 | +213.568 | SS-9536(?) | +210.845
STÅLSØYLE | 0.0049644 | 1.576 | 38.9706 | 2673 | DSS-7299(?) | +TI=221.038 | 72717 | 0.81794 | 0.00496 | 0.85738 | 38.6088 | 0.00492 | +213.568 | SS-9536(?) | +210.895
STÅLSØYLE | 0.00500107 | 1.59034 | 39.2584 | 2700 | DSS-7299(?) | +TI=221.038 | 72717 | 0.8262 | 0.00499 | 0.86529 | 38.9988 | 0.00498 | +213.595 | SS-0(?) | +210.895
STÅLSØYLE | 0.00442782 | 1.40904 | 34.7584 | 2395 | DSS-7299(?) | +TI=221.038 | 72717 | 0.73287 | 0.00443 | 0.76676 | 34.5934 | 0.00441 | +213.290 | SS-0(?) | +210.895
STÅLSØYLE | 0.00502671 | 1.60287 | 39.4597 | 2728 | DSS-7299(?) | +TI=221.038 | 72717 | 0.83477 | 0.00504 | 0.8721 | 39.4032 | 0.00501 | +213.573 | SS-0(?) | +210.845
4 x STÅLSØYLE | 0.00541386 | 1.71868 | 42.4988 | 2915 | DSS-7118(?) | +TI=221.025 | 72253 | 0.89199 | 0.00542 | 0.93482 | 42.1043 | 0.00535 | +213.795 | SS-8144(?) | +210.880

# IfcCovering (18)
PredefinedType: INSULATION
ePset_Simplebim - Assembly Level: Leaf
Name | In | Description | Splitting | Area, largest surface, net (Simplebim) (m2) | Volume, net (Simplebim) (m3) | Height (Simplebim) (mm) | Width (Simplebim) (mm) | Length (Simplebim) (mm) | User Code | SystemType | SystemClass | SystemName | NationalCode | Material
BI10T - Cellegummi 18-32 mm kalde rør | Nivå D | BI10T - Cellegummi 18-32 mm kalde rør | ORIGINAL | 0.245675 | 0.00320693 | 58 | 58 | 1350 | Cu | KJØLMEDIE R | Hydronic Return | 35= R 4° Kopi 2 | UB1.111713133 | Kobberrør | MagiCAD Pset_Pipe - qv_SizingFlow_ls: 0 m3/s; Insulation_thickness_mm: 20 mm; ConnectionSize_mm: 18 mm; Length_mm: 1350 mm; MagiCAD Pset_Heating - v_SizingFlow_ms: 0 m/s; pTot_SizingFlow_kPa: 0 kPa; dpTot_SizingFlow_kPa: 0 kPa; MagiCAD Pset_Water - dpTot_SizingFlow_kPa: 0 kPa; pTot_SizingFlow_kPa: 0 kPa; v_SizingFlow_ms: 0 m/s
BI10T - Cellegummi 18-32 mm kalde rør | Nivå D | BI10T - Cellegummi 18-32 mm kalde rør | ORIGINAL | 0.245675 | 0.00320693 | 58 | 58 | 1350 | Cu | KJØLMEDIE T | Hydronic Supply | 35= T 0° Kopi 2 | UB1.111713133 | Kobberrør | MagiCAD Pset_Pipe - qv_SizingFlow_ls: 0 m3/s; Insulation_thickness_mm: 20 mm; ConnectionSize_mm: 18 mm; Length_mm: 1350 mm; MagiCAD Pset_Heating - v_SizingFlow_ms: 0 m/s; pTot_SizingFlow_kPa: 0 kPa; dpTot_SizingFlow_kPa: 0 kPa; MagiCAD Pset_Water - dpTot_SizingFlow_kPa: 0 kPa; pTot_SizingFlow_kPa: 0 kPa; v_SizingFlow_ms: 0 m/s
2 x BI10T - Cellegummi 18-32 mm kalde rør | Nivå D | BI10T - Cellegummi 18-32 mm kalde rør | ORIGINAL | 0.00363385 | 0.00005224 | 20 | 58 | 58 | MagiCAD Pset_Joint - qv_SizingFlow_ls: 0 m3/s; pTot_SizingFlow_Pa: 0 kPa; dpTot_SizingFlow_Pa: 0 kPa; v_SizingFlow_ms: 0 m/s; ConnectionSize_mm: 0 mm; Insulation_thickness_mm: 20 mm
BI11T - Rørskål m/Al.folie - varme 60-25 | Nivå E | BI11T - Rørskål m/Al.folie - varme 60-25 | ORIGINAL | 0.0765968 | 0.00188947 | 105 | 105 | 232.5 | DN | GULVVARME T- | Hydronic Return | +TI=323.001 T | UB3.144613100 | Stålrør normaltykke | MagiCAD Pset_Pipe - qv_SizingFlow_ls: 0 m3/s; Insulation_thickness_mm: 40 mm; ConnectionSize_mm: 25 mm; Length_mm: 232.389 mm; MagiCAD Pset_Heating - v_SizingFlow_ms: 0 m/s; pTot_SizingFlow_kPa: 0 kPa; dpTot_SizingFlow_kPa: 0 kPa; MagiCAD Pset_Water - dpTot_SizingFlow_kPa: 0 kPa; pTot_SizingFlow_kPa: 0 kPa; v_SizingFlow_ms: 0 m/s
2 x BI11T - Rørskål m/Al.folie - varme 60-25 | Nivå E | BI11T - Rørskål m/Al.folie - varme 60-25 | ORIGINAL | 1.07516 | 0.0265216 | 105 | 105 | 3263.5 | DN | GULVVARME T- | Hydronic Return | +TI=323.001 T | UB3.144613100 | Stålrør normaltykke | MagiCAD Pset_Pipe - qv_SizingFlow_ls: 0 m3/s; Insulation_thickness_mm: 40 mm; ConnectionSize_mm: 25 mm; Length_mm: 3263.48 mm; MagiCAD Pset_Heating - v_SizingFlow_ms: 0 m/s; pTot_SizingFlow_kPa: 0 kPa; dpTot_SizingFlow_kPa: 0 kPa; MagiCAD Pset_Water - dpTot_SizingFlow_kPa: 0 kPa; pTot_SizingFlow_kPa: 0 kPa; v_SizingFlow_ms: 0 m/s
2 x BI11T - Rørskål m/Al.folie - varme 60-25 | Nivå E | BI11T - Rørskål m/Al.folie - varme 60-25 | ORIGINAL | 0.780925 | 0.0192636 | 105 | 105 | 2370.4 | DN | GULVVARME R | Hydronic Return | +TI=323.001 R | UB3.144613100 | Stålrør normaltykke | MagiCAD Pset_Pipe - qv_SizingFlow_ls: 0 m3/s; Insulation_thickness_mm: 40 mm; ConnectionSize_mm: 25 mm; Length_mm: 2370.43 mm; MagiCAD Pset_Heating - v_SizingFlow_ms: 0 m/s; pTot_SizingFlow_kPa: 0 kPa; dpTot_SizingFlow_kPa: 0 kPa; MagiCAD Pset_Water - dpTot_SizingFlow_kPa: 0 kPa; pTot_SizingFlow_kPa: 0 kPa; v_SizingFlow_ms: 0 m/s
BI11T - Rørskål m/Al.folie - varme 60-25 | Nivå E | BI11T - Rørskål m/Al.folie - varme 60-25 | ORIGINAL | 0.153984 | 0.00379844 | 105 | 105 | 467.4 | DN | GULVVARME T- | Hydronic Return | +TI=323.001 T | UB3.144613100 | Stålrør normaltykke | MagiCAD Pset_Pipe - qv_SizingFlow_ls: 0 m3/s; Insulation_thickness_mm: 40 mm; ConnectionSize_mm: 25 mm; Length_mm: 466.875 mm; MagiCAD Pset_Heating - v_SizingFlow_ms: 0 m/s; pTot_SizingFlow_kPa: 0 kPa; dpTot_SizingFlow_kPa: 0 kPa; MagiCAD Pset_Water - dpTot_SizingFlow_kPa: 0 kPa; pTot_SizingFlow_kPa: 0 kPa; v_SizingFlow_ms: 0 m/s
BI11T - Rørskål m/Al.folie - varme 60-25 | Nivå E | BI11T - Rørskål m/Al.folie - varme 60-25 | ORIGINAL | 0.0172631 | 0.000425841 | 105 | 105 | 52.4 | DN | GULVVARME T- | Hydronic Return | +TI=323.001 T | UB3.144613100 | Stålrør normaltykke | MagiCAD Pset_Pipe - qv_SizingFlow_ls: 0 m3/s; Insulation_thickness_mm: 40 mm; ConnectionSize_mm: 25 mm; Length_mm: 52.411 mm; MagiCAD Pset_Heating - v_SizingFlow_ms: 0 m/s; pTot_SizingFlow_kPa: 0 kPa; dpTot_SizingFlow_kPa: 0 kPa; MagiCAD Pset_Water - dpTot_SizingFlow_kPa: 0 kPa; pTot_SizingFlow_kPa: 0 kPa; v_SizingFlow_ms: 0 m/s
3 x BI11T - Rørskål m/Al.folie - varme 60-25 | Nivå E | BI11T - Rørskål m/Al.folie - varme 60-25 | ORIGINAL | 0.021304 | 0.000551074 | 90.7 | 90.7 | 113.8 | MagiCAD Pset_Elbow - qv_SizingFlow_ls: 0 m3/s; pTot_SizingFlow_Pa: 0 kPa; dpTot_SizingFlow_Pa: 0 kPa; v_SizingFlow_ms: 0 m/s; ConnectionSize_mm: 0 mm; Insulation_thickness_mm: 40 mm
2 x BI11T - Rørskål m/Al.folie - varme 60-25 | Nivå E | BI11T - Rørskål m/Al.folie - varme 60-25 | ORIGINAL | 0.0213038 | 0.000551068 | 90.7 | 90.7 | 113.8 | MagiCAD Pset_Elbow - qv_SizingFlow_ls: 0 m3/s; pTot_SizingFlow_Pa: 0 kPa; dpTot_SizingFlow_Pa: 0 kPa; v_SizingFlow_ms: 0 m/s; ConnectionSize_mm: 0 mm; Insulation_thickness_mm: 40 mm
BI11T - Rørskål m/Al.folie - varme 60-25 | Nivå E | BI11T - Rørskål m/Al.folie - varme 60-25 | RESULT | 0.00812673 | 0.00311335 | 104 | 104 | 384 | DN | GULVVARME T- | Hydronic Return | +TI=323.001 T | UB3.144613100 | Stålrør normaltykke
BI11T - Rørskål m/Al.folie - varme 60-25 | Nivå E | BI11T - Rørskål m/Al.folie - varme 60-25 | RESULT | 0.00812673 | 0.00311335 | 104 | 104 | 383 | DN | GULVVARME T- | Hydronic Return | +TI=323.001 T | UB3.144613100 | Stålrør normaltykke

# IfcCovering: Compound Ceiling:A255 - HI-G03 (3)
In: Nivå D
Type - PredefinedType: CEILING
Type - Pset_CoveringCommon - TotalThickness: 30 mm
AVINOR - 03_Ansvar: 72253; 08_Status: S4; 07_Fase: F90; 06_Omrade: TI; 05_ID-nummer: +TI=255.001-ID0005; 02_Prosjekt: T20100; 01_Lufthavnkode: ENGM
Pset_CoveringCommon - Reference: A255 - HI-G03; sets with these values: 2
ePset_Simplebim - Assembly Level: Leaf
ePset_SimplebimBasicQuantities - Height (Simplebim): 30 mm; Width (Simplebim): 1927 mm
ePset_LocationTool - Splitting: RESULT
Name (Compound Ceiling:A255 - HI-G03:...) | Volume, net (Simplebim) (m3) | Length (Simplebim) (mm) | Area, largest surface, net (Simplebim) (m2)
45464343 | 0.190723 | 3298 | 6.35738
45464329 | 0.62451 | 10800 | 20.817
45464336 | 0.183475 | 3173 | 6.11584

# IfcCurtainWall: Curtain Wall:A245 - IMK - Metal Kledning (2)
In: Nivå F
AVINOR - 08_Status: S4; 07_Fase: F90; 05_ID-nummer: +TI=245.050; 06_Omrade: TI; 03_Ansvar: 72717; 02_Prosjekt: T20100; 01_Lufthavnkode: ENGM
Pset_QuantityTakeOff - Reference: A245 - IMK - Metal Kledning
ePset_SimplebimBasicQuantities - Height: 500 mm
ePset_Simplebim - Assembly Level: Topmost
Pset_CurtainWallCommon - IsExternal: no; Reference: A245 - IMK - Metal Kledning
Name (Curtain Wall:A245 - IMK - Metal Kledning:...) | Width (mm) | Length (mm) | Volume, net (Simplebim) (m3)
58791128 | 5385.17 | 17426.4 | 0.546404
58911246 | 5385.68 | 17445.2 | 0.546741

# IfcDistributionControlElement: Brannalarm Røykdetektor under gulv
In: Nivå F
Type - Description: Brannalarm Røykdetektor i gulv
ePset_Simplebim - Assembly Level: Leaf
MagiCAD Pset_Device - System code: 542; User code: -TY; Host: +TI=542.301; Circuit order no: 12; Length [mm]: 0 mm; Width [mm]: 0 mm; Height [mm]: 0 mm; Installation Code: 2; Manufacturer: General
ePset_LocationTool - Splitting: ORIGINAL
Group: Brannalarm

# IfcDistributionControlElement: CONTROL UNIT
In: Nivå F
Type - Description: Nødåpner KAC
ePset_Simplebim - Assembly Level: Leaf
Pset_ElectricalDeviceCommon - IP_Code: IP20
MagiCAD Pset_Device - System code: 543; IP_Code: IP20; Product code: CONTROL UNIT; P1: -XS; Length [mm]: 0 mm; Manufacturer: General; Width [mm]: 58 mm; Height [mm]: 122 mm
ePset_LocationTool - Splitting: ORIGINAL
Group: Adgangskontroll, Innbruddsalarm

# IfcDistributionControlElement: SECURITY ALARM 3 (2)
In: Nivå F
Type - Description: Kortleser med tastatur
Pset_ElectricalDeviceCommon - IP_Code: IP44
ePset_LocationTool - Splitting: ORIGINAL
ePset_Simplebim - Assembly Level: Leaf
MagiCAD Pset_Device - System code: 543; Product code: Security alarm 3; P1: -QP; Length [mm]: 0 mm; Manufacturer: General; Width [mm]: 25 mm; Height [mm]: 140 mm; IP_Code: IP44
Group: Adgangskontroll, Innbruddsalarm

# IfcDistributionControlElement: Standard (3)
Type - Description: Brannalarm Multikriteriedetektor OT Blue
MagiCAD Pset_Device - System code: 542; User code: -TY; Length [mm]: 0 mm; Width [mm]: 0 mm; Height [mm]: 0 mm; Installation Code: 2
ePset_Simplebim - Assembly Level: Leaf
ePset_LocationTool - Splitting: ORIGINAL
Group: Brannalarm
Name | In | Host | Circuit order no | Description
Standard | Nivå F | +TI=542.301 | 158
2 x Standard | Nivå E | +TI=542.302 | 22 | Brannalarm Røykdetektor over himling

# IfcDistributionControlElement: Switch with one push button (2)
In: Nivå F
Type - Description: Åpneknapp
ePset_LocationTool - Splitting: ORIGINAL
MagiCAD Pset_Device - Product code: Switch with one push button; System code: 543; P1: -QG; Length [mm]: 0 mm; Manufacturer: General; Width [mm]: 10 mm; Height [mm]: 60 mm; IP_Code: IP21
ePset_Simplebim - Assembly Level: Leaf
Pset_ElectricalDeviceCommon - IP_Code: IP21
Group: Adgangskontroll, Innbruddsalarm

# IfcDoor: A233 - Rulleport:A233 - RI_AAO - 4080 x 2500, A233 - Rulleport:A233 - RI_AAO - 4080 x 2500:61153236
In: Nivå F
Type - ParameterTakesPrecedence: no; Sizeable: no; Material: NO_Aluminium
OverallHeight: 2500 mm; OverallWidth: 4080 mm
AVINOR - 08_Status: S4; 07_Fase: F90; 06_Omrade: TI; 05_ID-nummer: +TI=243.001-IR0034; 03_Ansvar: 72717; 02_Prosjekt: T20100; 01_Lufthavnkode: ENGM
ePset_LocationTool - Splitting: ORIGINAL
ePset_Simplebim - Assembly Level: Leaf
Pset_DoorCommon - IsExternal: yes; Reference: A233 - RI_AAO - 4080 x 2500
Pset_QuantityTakeOff - Reference: A233 - RI_AAO - 4080 x 2500
ePset_SimplebimBasicQuantities - Width, opening (Simplebim): 4080 mm; Height (Simplebim): 2500 mm; Height, opening (Simplebim): 2500 mm; Area, opening (Simplebim): 10.2 m2; Area (Simplebim): 10.125 m2; Width (Simplebim): 4050 mm; Length, frame (Simplebim): 9050 mm

# IfcDoor: A233 - Rulleport:A233 - RI_AAO - 4300 x 2500, A233 - Rulleport:A233 - RI_AAO - 4300 x 2500:61153468
In: Nivå F
Type - ParameterTakesPrecedence: no; Sizeable: no; Material: NO_Aluminium
OverallHeight: 2500 mm; OverallWidth: 4300 mm
Pset_QuantityTakeOff - Reference: A233 - RI_AAO - 4300 x 2500
ePset_Simplebim - Assembly Level: Leaf
ePset_LocationTool - Splitting: ORIGINAL
Pset_DoorCommon - IsExternal: yes; Reference: A233 - RI_AAO - 4300 x 2500
AVINOR - 08_Status: S4; 07_Fase: F90; 06_Omrade: TI; 03_Ansvar: 72717; 02_Prosjekt: T20100; 05_ID-nummer: +TI=243.001-IR0009; 01_Lufthavnkode: ENGM
ePset_SimplebimBasicQuantities - Height (Simplebim): 2500 mm; Height, opening (Simplebim): 2500 mm; Area, opening (Simplebim): 10.75 m2; Area (Simplebim): 10.675 m2; Width (Simplebim): 4270 mm; Width, opening (Simplebim): 4300 mm; Length, frame (Simplebim): 9270 mm

# IfcDoor: A233 - Rulleport:A233 - RI_AAO - 4305 x 2500 (2)
In: Nivå F
Type - ParameterTakesPrecedence: no; Sizeable: no; Material: NO_Aluminium
OverallHeight: 2500 mm; OverallWidth: 4305 mm
AVINOR - 08_Status: S4; 07_Fase: F90; 06_Omrade: TI; 03_Ansvar: 72717; 02_Prosjekt: T20100; 01_Lufthavnkode: ENGM
Pset_QuantityTakeOff - Reference: A233 - RI_AAO - 4305 x 2500
ePset_Simplebim - Assembly Level: Leaf
ePset_LocationTool - Splitting: ORIGINAL
Pset_DoorCommon - IsExternal: yes; Reference: A233 - RI_AAO - 4305 x 2500
ePset_SimplebimBasicQuantities - Width, opening (Simplebim): 4305 mm; Height (Simplebim): 2500 mm; Height, opening (Simplebim): 2500 mm; Area, opening (Simplebim): 10.7625 m2; Area (Simplebim): 10.6875 m2; Width (Simplebim): 4275 mm; Length, frame (Simplebim): 9275 mm
Name (A233 - Rulleport:A233 - RI_AAO - 4305 x 2500:...) | 05_ID-nummer
61153153 | +TI=243.001-IR0031
61153467 | +TI=243.001-IR0006

# IfcDoor: A233 - Rulleport:A233 - RI_AAO - 4500 x 2500 (4)
In: Nivå F
Type - ParameterTakesPrecedence: no; Sizeable: no; Material: NO_Aluminium
OverallHeight: 2500 mm; OverallWidth: 4500 mm
Pset_QuantityTakeOff - Reference: A233 - RI_AAO - 4500 x 2500
ePset_Simplebim - Assembly Level: Leaf
Pset_DoorCommon - Reference: A233 - RI_AAO - 4500 x 2500; IsExternal: yes
ePset_LocationTool - Splitting: ORIGINAL
AVINOR - 08_Status: S4; 07_Fase: F90; 06_Omrade: TI; 03_Ansvar: 72717; 02_Prosjekt: T20100; 01_Lufthavnkode: ENGM
ePset_SimplebimBasicQuantities - Height (Simplebim): 2500 mm; Height, opening (Simplebim): 2500 mm; Area (Simplebim): 11.175 m2; Area, opening (Simplebim): 11.25 m2; Width, opening (Simplebim): 4500 mm; Width (Simplebim): 4470 mm; Length, frame (Simplebim): 9470 mm
Name (A233 - Rulleport:A233 - RI_AAO - 4500 x 2500:...) | 05_ID-nummer
61152912 | +TI=243.001-IR0029
61153000 | +TI=243.001-IR0030
61153136 | +TI=243.001-IR0007
61153137 | +TI=243.001-IR0019

# IfcElectricalCircuit (5)
Name | Description
Kursopplegg driftsteknisk | 461
Kursopplegg for underfordelinger | 4332
Utstyr for nødlys | 443
Utstyr for virksomhet | 561
Adgangskontroll, Innbruddsalarm | 543

# IfcFlowController: Water-flow-meter-DN20 (2)
In: Nivå D
Type - Description: Flow meter; PredefinedType: FLOWMETER
MagiCAD Pset_PipeComponent - User Code: RF11T; Product Code: Water-flow-meter-DN20; qv_SizingFlow_ls: 0 m3/s; pTot_SizingFlow_Pa: 0 kPa; dpTot_SizingFlow_kPa: 0 kPa; Manufacturer: Generic; ConnectionSize_mm: 20 mm; Description: Flow meter
ePset_Simplebim - Assembly Level: Leaf
ePset_LocationTool - Splitting: ORIGINAL
Name | Group
Water-flow-meter-DN20 | +TI=310.101-16
Water-flow-meter-DN20 | +TI=310.201-1

# IfcFlowFitting: Junction box round1 (5)
In: Nivå F
Type - Description: Koblingsboks åpen tele-data
MagiCAD Pset_Device - System code: 543; Length [mm]: 0 mm; Width [mm]: 0 mm; Height [mm]: 0 mm; Product code: Junction box round1; Manufacturer: General
ePset_LocationTool - Splitting: ORIGINAL
ePset_Simplebim - Assembly Level: Leaf
Group: Adgangskontroll, Innbruddsalarm

# IfcFlowFitting: Junction box1 (4)
In: Nivå F
Type - Description: Koblingsboks åpen
Pset_ElectricalDeviceCommon - IP_Code: IP20; ElectricalDeviceNominalPower: 0 W; NumberOfPoles: 1; NominalVoltage: 230
MagiCAD Pset_Device - Switchboard: +TI=433.325; IP_Code: IP20; Length [mm]: 0 mm; Number of Poles: 1; Active Power: 0 W; Manufacturer: General; Power Factor: 1; Width [mm]: 46 mm; Height [mm]: 104 mm; Voltage: 230; Product code: Junction box1
ePset_LocationTool - Splitting: ORIGINAL
ePset_Simplebim - Assembly Level: Leaf
Name | Circuit order no
2 x Junction box1 | 9
2 x Junction box1 | 8

# IfcFlowFitting: Koblingsboks åpen (8)
Type - Description: Koblingsboks åpen
Pset_ElectricalDeviceCommon - IP_Code: IP20; ElectricalDeviceNominalPower: 0 W; NumberOfPoles: 1; NominalVoltage: 230
ePset_LocationTool - Splitting: ORIGINAL
ePset_Simplebim - Assembly Level: Leaf
MagiCAD Pset_Device - User code: -QM; IP_Code: IP20; Length [mm]: 0 mm; Number of Poles: 1; Active Power: 0 W; Manufacturer: General; Power Factor: 1; Width [mm]: 46 mm; Height [mm]: 104 mm; Voltage: 230
Name | In | System code | Circuit order no | Switchboard | Group
Koblingsboks åpen | Nivå F | 4332 | 38 | +TI=433.315 | Kursopplegg for underfordelinger
Koblingsboks åpen | Nivå F | 461 | 69 | +TI=433.325 | Kursopplegg driftsteknisk | MagiCAD Pset_Device - Installation Code: 3
Koblingsboks åpen | Nivå F | 463 |  |  | Utstyr for virksomhet | MagiCAD Pset_Device - Installation Code: 4
Koblingsboks åpen | Nivå D + 1,2 m | 4332 | 10 | +TI=433.323 | Kursopplegg for underfordelinger
Koblingsboks åpen | Nivå D + 1,2 m | 4332 | 12 | +TI=433.323 | Kursopplegg for underfordelinger
Koblingsboks åpen | Nivå D + 1,2 m | 4332 | 14 | +TI=433.323 | Kursopplegg for underfordelinger
Koblingsboks åpen | Nivå D + 1,2 m | 4332 | 13 | +TI=433.323 | Kursopplegg for underfordelinger
Koblingsboks åpen | Nivå D + 1,2 m | 4332 | 23 | +TI=433.323 | Kursopplegg for underfordelinger

# IfcFlowFitting: Trekkerør, glatt bend (50)
In: Nivå F
Type - PredefinedType: BEND
MagiCAD Pset_Conduit - System code: 4110; Diameter [mm]: 0 mm; Length [mm]: 0 mm
ePset_LocationTool - Splitting: ORIGINAL
ePset_Simplebim - Assembly Level: Leaf
Group: Trekkerør generelt

# IfcFlowFitting: XD - Binærinngang
In: Nivå F
Type - Description: Koblingsboks åpen
ePset_LocationTool - Splitting: ORIGINAL
MagiCAD Pset_Device - User code: -QM; P1: -XK; Length [mm]: 0 mm; Width [mm]: 0 mm; Height [mm]: 0 mm; Number of Poles: 1; Active Power: 0 W; Installation Code: 4; Manufacturer: General; Power Factor: 1; Voltage: 230; System code: 561
Pset_ElectricalDeviceCommon - ElectricalDeviceNominalPower: 0 W; NumberOfPoles: 1; NominalVoltage: 230
ePset_Simplebim - Assembly Level: Leaf
Group: Utstyr for virksomhet

# IfcFlowFitting: XD - KNX-DALI GATEWAY
In: Nivå F
Type - Description: Koblingsboks åpen
MagiCAD Pset_Device - User code: -QM; P1: -XD; Length [mm]: 0 mm; Width [mm]: 0 mm; Height [mm]: 0 mm; Number of Poles: 1; Active Power: 0 W; Installation Code: 4; Manufacturer: General; Power Factor: 1; Voltage: 230; System code: 561
Pset_ElectricalDeviceCommon - ElectricalDeviceNominalPower: 0 W; NumberOfPoles: 1; NominalVoltage: 230
ePset_LocationTool - Splitting: ORIGINAL
ePset_Simplebim - Assembly Level: Leaf
Group: Utstyr for virksomhet

# IfcFlowFitting: magi_pipe_cu_elbow_short_001 (2)
In: Nivå D
Type - PredefinedType: BEND
MagiCAD Pset_Elbow - Insulation_thickness_mm: 0 mm; qv_SizingFlow_ls: 0 m3/s; pTot_SizingFlow_Pa: 0 kPa; dpTot_SizingFlow_Pa: 0 kPa; v_SizingFlow_ms: 0 m/s; ConnectionSize_mm: 0 mm
ePset_LocationTool - Splitting: ORIGINAL
ePset_Simplebim - Assembly Level: Leaf
Group: +TI=310.101-16

# IfcFlowFitting: magi_pipe_cu_joint_001 (2)
In: Nivå D
Type - PredefinedType: CONNECTOR
ePset_LocationTool - Splitting: ORIGINAL
ePset_Simplebim - Assembly Level: Leaf
MagiCAD Pset_Joint - qv_SizingFlow_ls: 0 m3/s; pTot_SizingFlow_Pa: 0 kPa; dpTot_SizingFlow_Pa: 0 kPa; v_SizingFlow_ms: 0 m/s; ConnectionSize_mm: 0 mm; Insulation_thickness_mm: 20 mm
Name | Group
magi_pipe_cu_joint_001 | 35= R 4° Kopi 2
magi_pipe_cu_joint_001 | 35= T 0° Kopi 2

# IfcFlowFitting: magi_pipe_cu_reducer_centric_short_001 (4)
In: Nivå D
Type - PredefinedType: TRANSITION
MagiCAD Pset_Reduction - Insulation_thickness_mm: 0 mm; qv_SizingFlow_ls: 0 m3/s; pTot_SizingFlow_Pa: 0 kPa; dpTot_SizingFlow_Pa: 0 kPa; v_SizingFlow_ms: 0 m/s; ConnectionSize_mm: 0 mm
ePset_Simplebim - Assembly Level: Leaf
ePset_LocationTool - Splitting: ORIGINAL
Name | Group
2 x magi_pipe_cu_reducer_centric_short_001 | +TI=310.101-16
2 x magi_pipe_cu_reducer_centric_short_001 | +TI=310.201-1

# IfcFlowFitting: magi_pipe_elbow_short_001 (11)
In: Nivå F
Type - PredefinedType: BEND
MagiCAD Pset_Elbow - Insulation_thickness_mm: 0 mm; qv_SizingFlow_ls: 0 m3/s; pTot_SizingFlow_Pa: 0 kPa; dpTot_SizingFlow_Pa: 0 kPa; v_SizingFlow_ms: 0 m/s; ConnectionSize_mm: 0 mm
ePset_Simplebim - Assembly Level: Leaf
ePset_LocationTool - Splitting: ORIGINAL
Group: +TI=313.001

# IfcFlowFitting: magi_pipe_fe_elbow_short_001 (22)
Type - PredefinedType: BEND
MagiCAD Pset_Elbow - qv_SizingFlow_ls: 0 m3/s; pTot_SizingFlow_Pa: 0 kPa; dpTot_SizingFlow_Pa: 0 kPa; v_SizingFlow_ms: 0 m/s; ConnectionSize_mm: 0 mm
ePset_Simplebim - Assembly Level: Leaf
ePset_LocationTool - Splitting: ORIGINAL
Name | In | Insulation_thickness_mm (mm) | Group
2 x magi_pipe_fe_elbow_short_001 | Nivå F | 0 | +TI=323.001 T
3 x magi_pipe_fe_elbow_short_001 | Nivå F | 0 | +TI=323.001 R
4 x magi_pipe_fe_elbow_short_001 | Nivå E | 0 | +TI=323.001 T
6 x magi_pipe_fe_elbow_short_001 | Nivå E | 0 | +TI=323.001 R
5 x magi_pipe_fe_elbow_short_001 | Nivå E | 40 | +TI=323.001 T
2 x magi_pipe_fe_elbow_short_001 | Nivå D | 0 | +TI=332.001-NZ0006

# IfcFlowFitting: magi_pipe_fe_reducer_centric_short_NOR (21)
Type - PredefinedType: TRANSITION
MagiCAD Pset_Reduction - Insulation_thickness_mm: 0 mm; qv_SizingFlow_ls: 0 m3/s; pTot_SizingFlow_Pa: 0 kPa; dpTot_SizingFlow_Pa: 0 kPa; v_SizingFlow_ms: 0 m/s; ConnectionSize_mm: 0 mm
ePset_Simplebim - Assembly Level: Leaf
ePset_LocationTool - Splitting: ORIGINAL
Name | In | Group
2 x magi_pipe_fe_reducer_centric_short_NOR | Nivå F | +TI=323.001 T
2 x magi_pipe_fe_reducer_centric_short_NOR | Nivå F | +TI=323.001 R
magi_pipe_fe_reducer_centric_short_NOR | Nivå E | +TI=323.001 T
16 x magi_pipe_fe_reducer_centric_short_NOR | Nivå D | +TI=332.001-NZ0006

# IfcFlowFitting: magi_pipe_fe_tee_centric_90_NOR (6)
Type - PredefinedType: JUNCTION
MagiCAD Pset_TBranch - Insulation_thickness_mm: 0 mm; qv_SizingFlow_ls: 0 m3/s; pTot_SizingFlow_Pa: 0 kPa; dpTot_SizingFlow_Pa: 0 kPa; v_SizingFlow_ms: 0 m/s; ConnectionSize_mm: 0 mm
ePset_LocationTool - Splitting: ORIGINAL
ePset_Simplebim - Assembly Level: Leaf
Name | In | Group
magi_pipe_fe_tee_centric_90_NOR | Nivå F | +TI=323.001 T
2 x magi_pipe_fe_tee_centric_90_NOR | Nivå F | +TI=323.001 R
magi_pipe_fe_tee_centric_90_NOR | Nivå E | +TI=323.001 T
2 x magi_pipe_fe_tee_centric_90_NOR | Nivå D | +TI=332.001-NZ0006

# IfcFlowFitting: magi_sewer_bend_001 (13)
Type - PredefinedType: BEND
MagiCAD Pset_Elbow - Insulation_thickness_mm: 0 mm; qv_SizingFlow_ls: 0 m3/s; pTot_SizingFlow_Pa: 0 kPa; dpTot_SizingFlow_Pa: 0 kPa; v_SizingFlow_ms: 0 m/s; ConnectionSize_mm: 0 mm
ePset_Simplebim - Assembly Level: Leaf
ePset_LocationTool - Splitting: ORIGINAL
Name | In | Group
6 x magi_sewer_bend_001 | Nivå D | +TI=313.001-37
4 x magi_sewer_bend_001 | Nivå D | +TD=313.028
magi_sewer_bend_001 | Nivå D | +TI=313.001
magi_sewer_bend_001 | Nivå F | +TD=313.028
magi_sewer_bend_001 | Nivå E | +TD=313.028

# IfcFlowFitting: magi_sewer_tee_wye_NOR
In: Nivå D
Type - PredefinedType: JUNCTION
MagiCAD Pset_TBranch - Insulation_thickness_mm: 0 mm; qv_SizingFlow_ls: 0 m3/s; pTot_SizingFlow_Pa: 0 kPa; dpTot_SizingFlow_Pa: 0 kPa; v_SizingFlow_ms: 0 m/s; ConnectionSize_mm: 0 mm
ePset_LocationTool - Splitting: ORIGINAL
ePset_Simplebim - Assembly Level: Leaf
Group: +TI=313.001-37

# IfcFlowFitting: magi_sewer_tee_wye_NOR_2 (2)
In: Nivå F
Type - PredefinedType: JUNCTION
MagiCAD Pset_TBranch - Insulation_thickness_mm: 0 mm; qv_SizingFlow_ls: 0 m3/s; pTot_SizingFlow_Pa: 0 kPa; dpTot_SizingFlow_Pa: 0 kPa; v_SizingFlow_ms: 0 m/s; ConnectionSize_mm: 0 mm
ePset_Simplebim - Assembly Level: Leaf
ePset_LocationTool - Splitting: ORIGINAL
Group: +TI=313.001

# IfcFlowFitting: magi_sewer_union_001 (2)
In: Nivå D
Type - PredefinedType: CONNECTOR
MagiCAD Pset_Joint - Insulation_thickness_mm: 0 mm; qv_SizingFlow_ls: 0 m3/s; pTot_SizingFlow_Pa: 0 kPa; dpTot_SizingFlow_Pa: 0 kPa; v_SizingFlow_ms: 0 m/s; ConnectionSize_mm: 0 mm
ePset_LocationTool - Splitting: ORIGINAL
ePset_Simplebim - Assembly Level: Leaf
Name | Group
magi_sewer_union_001 | +TD=313.028
magi_sewer_union_001 | +TI=313.001-37

# IfcFlowFitting: magi_sewer_union_NOR
In: Nivå D
Type - PredefinedType: CONNECTOR
MagiCAD Pset_Joint - Insulation_thickness_mm: 0 mm; qv_SizingFlow_ls: 0 m3/s; pTot_SizingFlow_Pa: 0 kPa; dpTot_SizingFlow_Pa: 0 kPa; v_SizingFlow_ms: 0 m/s; ConnectionSize_mm: 0 mm
ePset_LocationTool - Splitting: ORIGINAL
ePset_Simplebim - Assembly Level: Leaf
Group: +TI=313.001-37

# IfcFlowSegment: Gulvkanal (4)
In: Nivå F
Type - PredefinedType: CABLETRAYSEGMENT
MagiCAD Pset_Cabletray - System code: 4115
ePset_SimplebimBasicQuantities - Height (Simplebim): 50 mm; Width (Simplebim): 350 mm
ePset_Simplebim - Assembly Level: Leaf
ePset_LocationTool - Splitting: RESULT
Group: GULVKANAL
Name | Length (Simplebim) (mm)
Gulvkanal | 7481
Gulvkanal | 7591
Gulvkanal | 7354
Gulvkanal | 7464

# IfcFlowSegment: Kobberrør (8)
In: Nivå D
Type - PredefinedType: RIGIDSEGMENT
Classification: UB1.111713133 Not defined (NS3420)
MagiCAD Pset_Pipe - User Code: Cu; NationalCode: UB1.111713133; Material: Kobberrør
ePset_Simplebim - Assembly Level: Leaf
Name | SystemName = Group | Insulation_thickness_mm (mm) | qv_SizingFlow_ls (m3/s) = MagiCAD Pset_Heating, v_SizingFlow_ms (m/s) = MagiCAD Pset_Heating, pTot_SizingFlow_kPa (kPa) = MagiCAD Pset_Heating, dpTot_SizingFlow_kPa (kPa) = MagiCAD Pset_Water, dpTot_SizingFlow_kPa (kPa) = MagiCAD Pset_Water, pTot_SizingFlow_kPa (kPa) = MagiCAD Pset_Water, v_SizingFlow_ms (m/s) | ConnectionSize_mm (mm) | SystemType | Length_mm (mm) | SystemClass | Length (Simplebim) (mm) | Height (Simplebim) (mm) = Width (Simplebim) (mm) | Splitting
Kobberrør | +TI=310.101-16 | 0 | 0 | 18 | KV | 1494.88 | Domestic Cold Water | 1494.9 | 18 | ORIGINAL
Kobberrør | +TI=310.201-1 | 0 | 0 | 18 | VV | 1494.88 | Domestic Hot Water | 1494.9 | 18 | ORIGINAL
Kobberrør | +TI=310.101-16 | 0 | 0 | 15 | KV | 4610 | Domestic Cold Water | 4610 | 15 | ORIGINAL
Kobberrør | +TI=310.101-16 | 0 | 0 | 15 | KV | 1182.2 | Domestic Cold Water | 1182.2 | 15 | ORIGINAL
Kobberrør | 35= R 4° Kopi 2 | 20 | 0 | 18 | KJØLMEDIE R | 1350 | Hydronic Return | 1350 | 18 | ORIGINAL
Kobberrør | 35= T 0° Kopi 2 | 20 | 0 | 18 | KJØLMEDIE T | 1350 | Hydronic Supply | 1350 | 18 | ORIGINAL
Kobberrør | +TI=310.201-1 | 0 | 0 | 18 | VV | 60 | Domestic Hot Water | 60.2 | 18 | ORIGINAL
Kobberrør | +TI=310.101-16 |  |  |  | KV |  | Domestic Cold Water | 425 | 16 | RESULT

# IfcFlowSegment: MA (21)
Type - PredefinedType: RIGIDSEGMENT
Classification: UB2.1115131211 Not defined (NS3420)
ePset_Simplebim - Assembly Level: Leaf
MagiCAD Pset_Pipe - User Code: MA; Material: MA; SystemType: SPV; SystemClass: Sanitary; NationalCode: UB2.1115131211
Name | In | MagiCAD Pset_Heating, v_SizingFlow_ms (m/s) = MagiCAD Pset_Heating, pTot_SizingFlow_kPa (kPa) = MagiCAD Pset_Heating, dpTot_SizingFlow_kPa (kPa) = MagiCAD Pset_Water, dpTot_SizingFlow_kPa (kPa) = MagiCAD Pset_Water, pTot_SizingFlow_kPa (kPa) = MagiCAD Pset_Water, v_SizingFlow_ms (m/s) = Insulation_thickness_mm (mm) = qv_SizingFlow_ls (m3/s) | Height (Simplebim) (mm) | Width (Simplebim) (mm) | Length (Simplebim) (mm) | Length_mm (mm) | SystemName = Group | ConnectionSize_mm (mm) | Splitting
MA | Nivå D | 0 | 75 | 75 | 1616 | 1616.49 | +TI=313.001-37 | 75 | ORIGINAL
MA | Nivå D | 0 | 75 | 75 | 831.2 | 831.206 | +TI=313.001-37 | 75 | ORIGINAL
MA | Nivå D | 0 | 75 | 75 | 889.9 | 889.882 | +TI=313.001-37 | 75 | ORIGINAL
MA | Nivå D | 0 | 75 | 75 | 94.1 | 94.057 | +TI=313.001-37 | 75 | ORIGINAL
MA | Nivå D | 0 | 40.8 | 75 | 75 | 40.767 | +TI=313.001-37 | 75 | ORIGINAL
MA | Nivå D | 0 | 75 | 75 | 1210.8 | 1210.83 | +TI=313.001-37 | 75 | ORIGINAL
MA | Nivå D | 0 | 75 | 75 | 380.6 | 380.553 | +TI=313.001-37 | 75 | ORIGINAL
MA | Nivå D | 0 | 75 | 75 | 210.5 | 210.225 | +TI=313.001-37 | 75 | ORIGINAL
MA | Nivå D | 0 | 75 | 75 | 103.3 | 103.326 | +TD=313.028 | 75 | ORIGINAL
MA | Nivå D | 0 | 75 | 75 | 194.7 | 194.703 | +TD=313.028 | 75 | ORIGINAL
MA | Nivå D | 0 | 75 | 75 | 840 | 840 | +TD=313.028 | 75 | ORIGINAL
MA | Nivå D | 0 | 75 | 74.6 | 75 | 75.234 | +TD=313.028 | 75 | ORIGINAL
MA | Nivå D | 0 | 75 | 75 | 605.6 | 605.596 | +TD=313.028 | 75 | ORIGINAL
MA | Nivå D | 0 | 75 | 75 | 2122.2 | 2122.21 | +TD=313.028 | 75 | ORIGINAL
MA | Nivå D | 0 | 75 | 75 | 866 | 865.975 | +TI=313.001 | 75 | ORIGINAL
MA | Nivå D | 0 | 75 | 75 | 86 | 85.827 | +TI=313.001 | 75 | ORIGINAL
MA | Nivå D | 0 | 40 | 75 | 75 | 40 | +TI=313.001-37 | 75 | ORIGINAL
MA | Nivå E | 0 | 110 | 110 | 127.3 | 126.742 | +TD=313.028 | 110 | ORIGINAL
MA | Nivå E | 0 | 75 | 75 | 253 | 253.049 | +TD=313.028 | 75 | ORIGINAL
MA | Nivå E |  | 76 | 76 | 3689 |  | +TD=313.028 |  | RESULT
MA | Nivå F |  | 110 | 110 | 3788 |  | +TD=313.028 |  | RESULT

# IfcFlowSegment: PP avløpsrør (19)
Type - PredefinedType: RIGIDSEGMENT
Classification: UB2.1114431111 Not defined (NS3420)
MagiCAD Pset_Heating - v_SizingFlow_ms: 0 m/s; pTot_SizingFlow_kPa: 0 kPa; dpTot_SizingFlow_kPa: 0 kPa
MagiCAD Pset_Water - dpTot_SizingFlow_kPa: 0 kPa; pTot_SizingFlow_kPa: 0 kPa; v_SizingFlow_ms: 0 m/s
MagiCAD Pset_Pipe - Material: PP avløpsrør; Insulation_thickness_mm: 0 mm; qv_SizingFlow_ls: 0 m3/s; User Code: PP; SystemType: SPV; NationalCode: UB2.1114431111; SystemClass: Sanitary
ePset_Simplebim - Assembly Level: Leaf
ePset_LocationTool - Splitting: ORIGINAL
Name | In | SystemName = Group | Length_mm (mm) | ConnectionSize_mm (mm) = Width (Simplebim) (mm) | Length (Simplebim) (mm) | Height (Simplebim) (mm)
PP avløpsrør | Nivå D | +TI=313.001-37 | 1423.39 | 75 | 1423.4 | 75
PP avløpsrør | Nivå D | +TI=313.001-37 | 40.4 | 75 | 75 | 40
PP avløpsrør | Nivå F | +TI=313.001 | 177.399 | 50 | 177.4 | 50
PP avløpsrør | Nivå F | +TI=313.001 | 962.301 | 50 | 962.3 | 50
PP avløpsrør | Nivå F | +TI=313.001 | 8.939 | 50 | 8.9 | 50
PP avløpsrør | Nivå F | +TI=313.001 | 39.289 | 50 | 39.3 | 50
PP avløpsrør | Nivå F | +TI=313.001 | 23.391 | 50 | 50 | 23.1
PP avløpsrør | Nivå F | +TI=313.001 | 3.354 | 50 | 3.1 | 50
PP avløpsrør | Nivå F | +TI=313.001 | 179.459 | 50 | 180.5 | 50
PP avløpsrør | Nivå F | +TI=313.001 | 4.327 | 50 | 4.1 | 50
PP avløpsrør | Nivå F | +TI=313.001 | 9.825 | 50 | 50 | 10.4
PP avløpsrør | Nivå F | +TI=313.001 | 13.695 | 50 | 50 | 13.5
PP avløpsrør | Nivå F | +TI=313.001 | 350.042 | 50 | 350 | 50
PP avløpsrør | Nivå F | +TI=313.001 | 18.981 | 50 | 19 | 50
PP avløpsrør | Nivå F | +TI=313.001 | 7.677 | 50 | 8 | 50
PP avløpsrør | Nivå F | +TI=313.001 | 576.453 | 50 | 576 | 50
PP avløpsrør | Nivå F | +TI=313.001 | 76.859 | 50 | 76.7 | 50
PP avløpsrør | Nivå F | +TI=313.001 | 166.065 | 50 | 166 | 50
PP avløpsrør | Nivå F | +TI=313.001 | 80.988 | 50 | 81 | 50

# IfcFlowSegment: Stålrør normaltykke (54)
Type - PredefinedType: RIGIDSEGMENT
Classification: UB3.144613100 Not defined (NS3420)
ePset_Simplebim - Assembly Level: Leaf
MagiCAD Pset_Pipe - NationalCode: UB3.144613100; User Code: DN; Material: Stålrør normaltykke
Name | In | MagiCAD Pset_Heating, v_SizingFlow_ms (m/s) = MagiCAD Pset_Heating, pTot_SizingFlow_kPa (kPa) = MagiCAD Pset_Heating, dpTot_SizingFlow_kPa (kPa) = MagiCAD Pset_Water, dpTot_SizingFlow_kPa (kPa) = MagiCAD Pset_Water, pTot_SizingFlow_kPa (kPa) = MagiCAD Pset_Water, v_SizingFlow_ms (m/s) = qv_SizingFlow_ls (m3/s) | Height (Simplebim) (mm) | Width (Simplebim) (mm) | Length (Simplebim) (mm) | Splitting | SystemClass | SystemType | SystemName = Group | Insulation_thickness_mm (mm) | ConnectionSize_mm (mm) | Length_mm (mm)
2 x Stålrør normaltykke | Nivå F | 0 | 33.8 | 33.8 | 30.7 | ORIGINAL | Hydronic Return | GULVVARME T- | +TI=323.001 T | 0 | 25 | 31.2
Stålrør normaltykke | Nivå F | 0 | 26.6 | 26.6 | 112.8 | ORIGINAL | Hydronic Return | GULVVARME T- | +TI=323.001 T | 0 | 20 | 112.85
Stålrør normaltykke | Nivå F | 0 | 26.6 | 26.6 | 253 | ORIGINAL | Hydronic Return | GULVVARME T- | +TI=323.001 T | 0 | 20 | 253.2
2 x Stålrør normaltykke | Nivå F | 0 | 33.8 | 33.8 | 35.4 | ORIGINAL | Hydronic Return | GULVVARME R | +TI=323.001 R | 0 | 25 | 35
Stålrør normaltykke | Nivå F | 0 | 33.8 | 33.8 | 61.2 | ORIGINAL | Hydronic Return | GULVVARME R | +TI=323.001 R | 0 | 25 | 61.2
Stålrør normaltykke | Nivå F | 0 | 26.6 | 26.6 | 147.8 | ORIGINAL | Hydronic Return | GULVVARME R | +TI=323.001 R | 0 | 20 | 147.85
Stålrør normaltykke | Nivå F | 0 | 26.6 | 26.6 | 275.7 | ORIGINAL | Hydronic Return | GULVVARME R | +TI=323.001 R | 0 | 20 | 275.7
Stålrør normaltykke | Nivå F | 0 | 26.6 | 26.6 | 241.3 | ORIGINAL | Hydronic Return | GULVVARME T- | +TI=323.001 T | 0 | 20 | 240.972
Stålrør normaltykke | Nivå F | 0 | 33.8 | 33.8 | 28.2 | ORIGINAL | Hydronic Return | GULVVARME R | +TI=323.001 R | 0 | 25 | 28.2
Stålrør normaltykke | Nivå F | 0 | 33.8 | 33.8 | 56.3 | ORIGINAL | Hydronic Return | GULVVARME R | +TI=323.001 R | 0 | 25 | 56.2
Stålrør normaltykke | Nivå F | 0 | 26.6 | 26.6 | 280 | ORIGINAL | Hydronic Return | GULVVARME R | +TI=323.001 R | 0 | 20 | 280
Stålrør normaltykke | Nivå F | 0 | 33.8 | 33.8 | 139.4 | ORIGINAL | Hydronic Return | GULVVARME R | +TI=323.001 R | 0 | 25 | 139.4
Stålrør normaltykke | Nivå F | 0 | 26.6 | 26.6 | 97.4 | ORIGINAL | Hydronic Return | GULVVARME T- | +TI=323.001 T | 0 | 20 | 97.4
Stålrør normaltykke | Nivå E | 0 | 33.8 | 33.8 | 466.9 | ORIGINAL | Hydronic Return | GULVVARME T- | +TI=323.001 T | 0 | 25 | 466.875
2 x Stålrør normaltykke | Nivå E | 0 | 33.8 | 33.8 | 11.9 | ORIGINAL | Hydronic Return | GULVVARME T- | +TI=323.001 T | 0 | 25 | 12.5
2 x Stålrør normaltykke | Nivå E | 0 | 33.8 | 33.8 | 466.9 | ORIGINAL | Hydronic Return | GULVVARME R | +TI=323.001 R | 0 | 25 | 466.888
Stålrør normaltykke | Nivå E | 0 | 33.8 | 33.8 | 232.4 | ORIGINAL | Hydronic Return | GULVVARME T- | +TI=323.001 T | 40 | 25 | 232.389
2 x Stålrør normaltykke | Nivå E | 0 | 33.8 | 33.8 | 3263.5 | ORIGINAL | Hydronic Return | GULVVARME T- | +TI=323.001 T | 40 | 25 | 3263.48
2 x Stålrør normaltykke | Nivå E | 0 | 33.8 | 33.8 | 2370.4 | ORIGINAL | Hydronic Return | GULVVARME R | +TI=323.001 R | 40 | 25 | 2370.43
Stålrør normaltykke | Nivå E | 0 | 33.8 | 33.8 | 466.9 | ORIGINAL | Hydronic Return | GULVVARME T- | +TI=323.001 T | 40 | 25 | 466.875
Stålrør normaltykke | Nivå E | 0 | 33.8 | 33.8 | 51.7 | ORIGINAL | Hydronic Return | GULVVARME T- | +TI=323.001 T | 40 | 25 | 52.411
Stålrør normaltykke | Nivå E | 0 | 25.4 | 33.8 | 33.8 | ORIGINAL | Hydronic Return | GULVVARME T- | +TI=323.001 T | 0 | 25 | 24.65
Stålrør normaltykke | Nivå D | 0 | 31.5 | 33.8 | 33.8 | ORIGINAL | Fire Protection Wet | Sprinkel | +TI=332.001-NZ0006 | 0 | 25 | 32.348
Stålrør normaltykke | Nivå D | 0 | 48.2 | 48.2 | 2889 | ORIGINAL | Fire Protection Wet | Sprinkel | +TI=332.001-NZ0006 | 0 | 40 | 2889
Stålrør normaltykke | Nivå D | 0 | 33.8 | 33.8 | 16.7 | ORIGINAL | Fire Protection Wet | Sprinkel | +TI=332.001-NZ0006 | 0 | 25 | 16.767
Stålrør normaltykke | Nivå D | 0 | 48.2 | 48.2 | 2964 | ORIGINAL | Fire Protection Wet | Sprinkel | +TI=332.001-NZ0006 | 0 | 40 | 2964
Stålrør normaltykke | Nivå D | 0 | 48.2 | 48.2 | 192.8 | ORIGINAL | Fire Protection Wet | Sprinkel | +TI=332.001-NZ0006 | 0 | 40 | 193.2
Stålrør normaltykke | Nivå D | 0 | 48.2 | 48.2 | 198.8 | ORIGINAL | Fire Protection Wet | Sprinkel | +TI=332.001-NZ0006 | 0 | 40 | 198.781
Stålrør normaltykke | Nivå D |  | 48 | 48 | 864 | RESULT | Fire Protection Wet | Sprinkel | +TI=332.001-NZ0006
Stålrør normaltykke | Nivå E |  | 24 | 24 | 384 | RESULT | Hydronic Return | GULVVARME R | +TI=323.001 R
Stålrør normaltykke | Nivå E |  | 34 | 34 | 384 | RESULT | Hydronic Return | GULVVARME T- | +TI=323.001 T
4 x Stålrør normaltykke | Nivå D |  | 34 | 34 | 423 | RESULT | Fire Protection Wet | Sprinkel | +TI=332.001-NZ0006
Stålrør normaltykke | Nivå D |  | 48 | 48 | 679 | RESULT | Fire Protection Wet | Sprinkel | +TI=332.001-NZ0006
Stålrør normaltykke | Nivå E |  | 24 | 24 | 383 | RESULT | Hydronic Return | GULVVARME R | +TI=323.001 R
5 x Stålrør normaltykke | Nivå D |  | 34 | 34 | 424 | RESULT | Fire Protection Wet | Sprinkel | +TI=332.001-NZ0006
Stålrør normaltykke | Nivå E |  | 34 | 34 | 383 | RESULT | Hydronic Return | GULVVARME T- | +TI=323.001 T
Stålrør normaltykke | Nivå F |  | 26 | 26 | 1645 | RESULT | Hydronic Return | GULVVARME R | +TI=323.001 R
2 x Stålrør normaltykke | Nivå F |  | 26 | 26 | 921 | RESULT | Hydronic Return | GULVVARME T- | +TI=323.001 T
Stålrør normaltykke | Nivå F |  | 26 | 26 | 1485 | RESULT | Hydronic Return | GULVVARME R | +TI=323.001 R
Stålrør normaltykke | Nivå D |  | 34 | 34 | 360 | RESULT | Fire Protection Wet | Sprinkel | +TI=332.001-NZ0006

# IfcFlowSegment: Trekkerør, korrugert (70)
In: Nivå F
Type - PredefinedType: CONDUITSEGMENT
ePset_Simplebim - Assembly Level: Leaf
MagiCAD Pset_Conduit - System code: 4110; Diameter [mm]: 25 mm
Pset_CableCarrierSegmentTypeConduitSegment - NominalWidth: 25 mm; NominalHeight: 25 mm
ePset_SimplebimBasicQuantities - Height (Simplebim): 25 mm; Width (Simplebim): 25 mm
ePset_LocationTool - Splitting: ORIGINAL
Group: Trekkerør generelt
Name | Length [mm] (mm) = NominalLength (mm) | Length (Simplebim) (mm)
Trekkerør, korrugert | 663.548 | 664
Trekkerør, korrugert | 188.202 | 188.5
Trekkerør, korrugert | 2103.8 | 2103.8
Trekkerør, korrugert | 638.094 | 637.6
Trekkerør, korrugert | 163.006 | 163
Trekkerør, korrugert | 2071.36 | 2071.4
4 x Trekkerør, korrugert | 2055.33 | 2055.3
Trekkerør, korrugert | 377.217 | 376.9
Trekkerør, korrugert | 949.432 | 949.1
Trekkerør, korrugert | 328.779 | 328.8
2 x Trekkerør, korrugert | 930.819 | 931.2
Trekkerør, korrugert | 1862.7 | 1862.7
Trekkerør, korrugert | 275.326 | 275.3
Trekkerør, korrugert | 219.646 | 219.6
Trekkerør, korrugert | 2109.94 | 2109.7
2 x Trekkerør, korrugert | 1817.53 | 1818.1
Trekkerør, korrugert | 238.596 | 238.9
Trekkerør, korrugert | 209.161 | 209.1
Trekkerør, korrugert | 2061.04 | 2061
4 x Trekkerør, korrugert | 3382.93 | 3382.9
Trekkerør, korrugert | 1697.21 | 1697.2
Trekkerør, korrugert | 1825.27 | 1825.3
Trekkerør, korrugert | 1753.56 | 1753.6
Trekkerør, korrugert | 1845.82 | 1845.8
4 x Trekkerør, korrugert | 4182.79 | 4182.8
2 x Trekkerør, korrugert | 227.465 | 228.1
Trekkerør, korrugert | 618.74 | 618.9
Trekkerør, korrugert | 306.042 | 306.5
2 x Trekkerør, korrugert | 285.896 | 286
Trekkerør, korrugert | 643.242 | 643.3
Trekkerør, korrugert | 311.042 | 310.9
Trekkerør, korrugert | 637.585 | 637.6
Trekkerør, korrugert | 234.436 | 234.5
2 x Trekkerør, korrugert | 2121.36 | 2120.7
Trekkerør, korrugert | 637.839 | 637.6
Trekkerør, korrugert | 163.366 | 163
Trekkerør, korrugert | 384.346 | 383.7
Trekkerør, korrugert | 945.531 | 945.5
Trekkerør, korrugert | 329.302 | 328.8
Trekkerør, korrugert | 358.773 | 358.9
Trekkerør, korrugert | 107.782 | 108
Trekkerør, korrugert | 2122.43 | 2122.4
Trekkerør, korrugert | 1806.08 | 1805.9
Trekkerør, korrugert | 317.361 | 317.3
Trekkerør, korrugert | 22.168 | 21.5
Trekkerør, korrugert | 2160.34 | 2159.8
Trekkerør, korrugert | 1706.26 | 1705.5
Trekkerør, korrugert | 1775.82 | 1775.6
Trekkerør, korrugert | 1784.98 | 1785.2
Trekkerør, korrugert | 1785.02 | 1785.2
Trekkerør, korrugert | 574.555 | 574.6
Trekkerør, korrugert | 338.673 | 339.2
Trekkerør, korrugert | 655.701 | 656.3
Trekkerør, korrugert | 296.13 | 296.3
Trekkerør, korrugert | 200.367 | 200
Trekkerør, korrugert | 245.507 | 246

# IfcFlowTerminal: IB7334 Zumtobel Puresign/Consign 150 ASI NDA (2)
In: Nivå F
Type - Description: Markeringslys ensidig 30 meter leseavstand wire
Pset_ElectricalDeviceCommon - NumberOfPoles: 1; ElectricalDeviceNominalPower: 4.5 W; NominalVoltage: 230
MagiCAD Pset_Device - User code: IB7334; System code: 443; Manufacturer: Zumtobel; Switchboard: +TI=443.471; Length [mm]: 0 mm; Width [mm]: 0 mm; Height [mm]: 0 mm; Number of Poles: 1; Circuit order no: 8; Power Factor: 1; Active Power: 4.5 W; Voltage: 230
Pset_LightFixtureTypeCommon - TotalWattage: 4.5 W
ePset_Simplebim - Assembly Level: Leaf
ePset_LocationTool - Splitting: ORIGINAL
Group: Utstyr for nødlys

# IfcFlowTerminal: Jordet-topolet-1-veis-Påvegg
In: Nivå F
Type - Description: Jordet topolet 1-veis Påvegg; PredefinedType: POWEROUTLET
Classification: WL1.2111 Not defined (NS3420); Group: Kursopplegg for underfordelinger
Pset_ElectricalDeviceCommon - NumberOfPoles: 1; IP_Code: 20; ElectricalDeviceNominalPower: 150 W; NominalVoltage: 230
Pset_OutletTypeCommon - IsPluggableOutlet: yes
ePset_LocationTool - Splitting: ORIGINAL
MagiCAD Pset_Device - Switchboard: +TI=433.425; National code: WL1.2111; Circuit order no: 42; System code: 4332; Length [mm]: 0 mm; Width [mm]: 0 mm; Height [mm]: 0 mm; Number of Poles: 1; IP_Code: 20; User code: 50; P1: -UE; Manufacturer: General; Power Factor: 1; Active Power: 150 W; Voltage: 230
ePset_Simplebim - Assembly Level: Leaf

# IfcFlowTerminal: Jordet-topolet-2-veis m_boks-EDB (4)
In: Nivå F
Type - Description: Jordet topolet 2-veis m/boks EDB; PredefinedType: POWEROUTLET
Classification: WL1.2111 Not defined (NS3420); Group: Utstyr for virksomhet
Pset_OutletTypeCommon - IsPluggableOutlet: yes
Pset_ElectricalDeviceCommon - IP_Code: IP20; ElectricalDeviceNominalPower: 0 W; NumberOfPoles: 1; NominalVoltage: 230
ePset_LocationTool - Splitting: ORIGINAL
MagiCAD Pset_Device - National code: WL1.2111; IP_Code: IP20; Product code: Recessed socket 2 horizontal; Length [mm]: 0 mm; Number of Poles: 1; Active Power: 0 W; Installation Code: 4; P1: -UE; Manufacturer: General; Power Factor: 1; Width [mm]: 11 mm; Height [mm]: 85 mm; Voltage: 230; System code: 463
ePset_Simplebim - Assembly Level: Leaf
Name | Circuit order no | Switchboard
2 x Jordet-topolet-2-veis m_boks-EDB | 45 | +TI=433.315
2 x Jordet-topolet-2-veis m_boks-EDB | 44 | +TI=433.325

# IfcFlowTerminal: Jordet-topolet-4-veis m_boks-i-gulv
In: Nivå F
Type - PredefinedType: POWEROUTLET
Pset_OutletTypeCommon - IsPluggableOutlet: yes
MagiCAD Pset_Device - Circuit order no: 32; Length [mm]: 0 mm; Width [mm]: 0 mm; Height [mm]: 0 mm; Number of Poles: 1; Active Power: 0 W; Installation Code: 4; Power Factor: 1; Voltage: 230; Switchboard: +TI=433.245; System code: 463
Pset_ElectricalDeviceCommon - ElectricalDeviceNominalPower: 0 W; NumberOfPoles: 1; NominalVoltage: 230
ePset_LocationTool - Splitting: ORIGINAL
ePset_Simplebim - Assembly Level: Leaf
Group: Utstyr for virksomhet

# IfcFlowTerminal: Motor rullegitter (4)
In: Nivå F
Type - Description: Motor rullegitter
MagiCAD Pset_Device - Switchboard: +TI=433.325; Length [mm]: 0 mm; Width [mm]: 0 mm; Height [mm]: 0 mm; Number of Poles: 1; Active Power: 0 W; Manufacturer: General; Power Factor: 1; Voltage: 230
Pset_ElectricalDeviceCommon - ElectricalDeviceNominalPower: 0 W; NumberOfPoles: 1; NominalVoltage: 230
ePset_Simplebim - Assembly Level: Leaf
ePset_LocationTool - Splitting: ORIGINAL
Name | Circuit order no
2 x Motor rullegitter | 9
2 x Motor rullegitter | 8

# IfcFlowTerminal: SP-15-K80-68DGR-STD-STÅENDE (16)
In: Nivå D
Type - Description: Spray, pendent installation, STD, K=80
Classification: RS1.3000121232 Not defined (NS3420); Group: +TI=332.001-NZ0006
MagiCAD Pset_Sprinkler - User Code: UZ03T; NationalCode: RS1.3000121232; Product code: SP-15-K80-68DGR-STD; Description: Spray, pendent installation, STD, K=80; Manufacturer: General; KFactor: 80; Nominal Release Temperature [°C]: 68
ePset_LocationTool - Splitting: ORIGINAL
ePset_Simplebim - Assembly Level: Leaf

# IfcMember: RHS80*6.3 (4)
In: F
Description: RHS80*6.3
ePset_LocationTool - Splitting: ORIGINAL
ePset_Simplebim - Assembly Level: Leaf
AVINOR - 08_Status: S4; 07_Fase: F90; 06_Omrade: TI; 05_ID-nummer: +TI=221.038; 04_Kontrakt: 72717; 02_Prosjekt: T20100; 03_Ansvar: 72101; 01_Lufthavnkode: ENGM
Pset_MemberCommon - LoadBearing: no
ePset_SimplebimBasicQuantities - Width (Simplebim): 80 mm; Length (Simplebim): 80 mm
Tekla Quantity - Heigth: 80 mm; Width: 80 mm
Tekla Common - Profile: RHS80*6.3; Name: STÅLDIAGONAL; Class: 331
Name | Material | Reference = Part mark | Area, sides, net (Simplebim) (m2) | Height (Simplebim) (mm) = Length (mm) | Weight, as steel (Simplebim) (kg) = WEIGTH_NET (kg) | Volume, net (Simplebim) (m3) | VOLUME_NET (m3) | WEIGTH_GROSS (kg) | AREA_GROSS (m2) | VOLUME_GROSS (m3) | AREA_NET (m2) | Grade | Assembly mark | Bottom elevation | Top elevation
2 x STÅLDIAGONAL | STEEL/S355 | DSD-1425(?) | 1.46716 | 2637.37 | 36.0485 | 0.00459217 | 0.00459 | 38.0941 | 0.80702 | 0.00485 | 0.79629 | S355 | SS-0(?) | +210.895 | +213.448
STÅLDIAGONAL | STEEL/S355J2H | DSD-1419(?) | 1.75016 | 2967.11 | 43.0606 | 0.00548543 | 0.00549 | 42.8569 | 0.90793 | 0.00545 | 0.94988 | S355J2H | SD-786(?) | +210.967 | +213.178
STÅLDIAGONAL | STEEL/S355 | DSD-1425(?) | 1.45157 | 2645.63 | 35.6191 | 0.00453747 | 0.00454 | 38.2135 | 0.80956 | 0.00487 | 0.78782 | S355 | SS-0(?) | +210.895 | +213.486

# IfcPlate: PL12*200 (5)
In: F
Description: PL12*200; Material: STEEL/S355
ePset_SimplebimBasicQuantities - Weight, as steel (Simplebim): 5.64778 kg; Volume, net (Simplebim): 0.000719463 m3; Area, largest surface, net (Simplebim): 0.0599553 m2
Pset_PlateCommon - Reference: DSB-12259; LoadBearing: no
Tekla Quantity - Heigth: 200.004 mm; AREA_GROSS: 0.06 m2; WEIGTH_NET: 5.64778 kg; VOLUME_GROSS: 0.00072 m3; VOLUME_NET: 0.00072 m3; WEIGTH_GROSS: 5.65212 kg; Width: 12 mm; Length: 300 mm; AREA_NET: 0.13191 m2
ePset_Simplebim - Assembly Level: Leaf
Tekla Common - Top elevation: +210.465; Grade: S355; Name: STÅLBJELKE; Class: 320; Part mark: DSB-12259; Profile: PL12*200; Bottom elevation: +210.453; Assembly mark: SB-7035
AVINOR - 08_Status: S4; 07_Fase: F40; 06_Omrade: TI; 05_ID-nummer: +TI=223.008; 04_Kontrakt: 72242; 03_Ansvar: 72242; 02_Prosjekt: T20100; 01_Lufthavnkode: ENGM
ePset_LocationTool - Splitting: ORIGINAL

# IfcPlate: System Panel:A245 - KL- X - butikkfasade avklares (10)
In: Nivå F
Type - PredefinedType: CURTAIN_PANEL; Material: Metal - Preget plate
AVINOR - 08_Status: S4; 07_Fase: F90; 05_ID-nummer: +TI=245.050; 06_Omrade: TI; 03_Ansvar: 72717; 02_Prosjekt: T20100; 01_Lufthavnkode: ENGM
Pset_QuantityTakeOff - Reference: A245 - KL- X - butikkfasade avklares
ePset_Simplebim - Assembly Level: Leaf
Pset_PlateCommon - Reference: A245 - KL- X - butikkfasade avklares; IsExternal: no
Name (System Panel:A245 - KL- X - butikkfasade avklares:...) | Splitting | Volume, net (Simplebim) (m3) | Weight, as steel (Simplebim) (kg) | Area, largest surface, net (Simplebim) (m2)
59335349 | ORIGINAL | 0.019944 | 156.56 | 0.336977
68560747 | ORIGINAL | 0.078 | 612.3 | 1.3
68560753 | ORIGINAL | 0.075 | 588.75 | 1.25
68560744 | ORIGINAL | 0.0779403 | 611.832 | 1.29901
68562834 | ORIGINAL | 0.078 | 612.3 | 1.3
68562837 | ORIGINAL | 0.075 | 588.75 | 1.25
68562840 | ORIGINAL | 0.078 | 612.3 | 1.3
68562843 | ORIGINAL | 0.0202208 | 158.733 | 0.337013
68560727 | RESULT | 0.0156887 | 123.156 | 0.266065
68562828 | RESULT | 0.015628 | 122.68 | 0.265053

# IfcSlab: 150*12000, PÅSTØP
In: F
Description: 150*12000; PredefinedType: FLOOR
AVINOR - 08_Status: S4; 07_Fase: F40; 05_ID-nummer: +TI=251.006; 06_Omrade: TI; 04_Kontrakt: 72242; 03_Ansvar: 72242; 02_Prosjekt: T20100; 01_Lufthavnkode: ENGM
ePset_LocationTool - Splitting: RESULT
Tekla Common - Name: PÅSTØP; Bottom elevation: +210.530; Part mark: Concrete-12853; Profile: 150*12000; Assembly mark: PST-666; Class: 262; Top elevation: +210.680; Grade: B30
ePset_Simplebim - Assembly Level: Leaf
Pset_SlabCommon - Reference: Concrete-12853; LoadBearing: no
ePset_SimplebimBasicQuantities - Area, top, net (Simplebim): 31.95 m2; Area, largest surface, net (Simplebim): 31.95 m2; Volume, net (Simplebim): 4.7925 m3; Thickness (Simplebim): 150 mm; Perimeter (Simplebim): 29325 mm; Area, sides, net (Simplebim): 4.39874 m2

# IfcSlab: 150*12435 (2)
In: F
Description: 150*12435; PredefinedType: FLOOR
AVINOR - 08_Status: S4; 07_Fase: F40; 05_ID-nummer: +TI=251.006; 06_Omrade: TI; 04_Kontrakt: 72242; 03_Ansvar: 72242; 02_Prosjekt: T20100; 01_Lufthavnkode: ENGM
ePset_SimplebimBasicQuantities - Thickness (Simplebim): 150 mm
ePset_Simplebim - Assembly Level: Leaf
ePset_LocationTool - Splitting: RESULT
Tekla Common - Name: PÅSTØP; Top elevation: +210.830; Profile: 150*12435; Class: 262; Bottom elevation: +210.680; Grade: B30
Pset_SlabCommon - LoadBearing: no
Name | Area, sides, net (Simplebim) (m2) | Volume, net (Simplebim) (m3) | Area, largest surface, net (Simplebim) (m2) = Area, top, net (Simplebim) (m2) | Perimeter (Simplebim) (mm) | Part mark = Reference | Assembly mark
PÅSTØP | 2.49323 | 2.07649 | 13.8432 | 16621.5 | Concrete-2310 | PST-151
PÅSTØP | 2.45563 | 2.03019 | 13.5346 | 16370.9 | Concrete-12852 | PST-761

# IfcSlab: 150*14550, PÅSTØP
In: F
Description: 150*14550; PredefinedType: FLOOR
ePset_SimplebimBasicQuantities - Area, largest surface, net (Simplebim): 104.757 m2; Perimeter (Simplebim): 47638.9 mm; Volume, net (Simplebim): 15.7135 m3; Area, sides, net (Simplebim): 7.14583 m2; Area, top, net (Simplebim): 104.757 m2; Thickness (Simplebim): 150 mm
AVINOR - 08_Status: S4; 07_Fase: F40; 05_ID-nummer: +TI=251.006; 06_Omrade: TI; 04_Kontrakt: 72242; 03_Ansvar: 72242; 02_Prosjekt: T20100; 01_Lufthavnkode: ENGM
ePset_Simplebim - Assembly Level: Leaf
ePset_LocationTool - Splitting: RESULT
Pset_SlabCommon - LoadBearing: no; Reference: Concrete-12851
Tekla Common - Name: PÅSTØP; Bottom elevation: +210.530; Grade: C30/37; Part mark: Concrete-12851; Assembly mark: PST-664; Profile: 150*14550; Class: 262; Top elevation: +210.680

# IfcSlab: 150*15250 (2)
In: F
Description: 150*15250; PredefinedType: FLOOR
AVINOR - 08_Status: S4; 07_Fase: F40; 05_ID-nummer: +TI=251.006; 06_Omrade: TI; 04_Kontrakt: 72242; 03_Ansvar: 72242; 02_Prosjekt: T20100; 01_Lufthavnkode: ENGM
Tekla Common - Name: PÅSTØP; Top elevation: +210.830; Grade: C30/37; Profile: 150*15250; Class: 262; Bottom elevation: +210.680
ePset_SimplebimBasicQuantities - Thickness (Simplebim): 150 mm
ePset_Simplebim - Assembly Level: Leaf
ePset_LocationTool - Splitting: RESULT
Pset_SlabCommon - LoadBearing: no
Name | Assembly mark | Part mark = Reference | Perimeter (Simplebim) (mm) | Area, sides, net (Simplebim) (m2) | Volume, net (Simplebim) (m3) | Area, largest surface, net (Simplebim) (m2) = Area, top, net (Simplebim) (m2)
PÅSTØP | PST-440 | Concrete-8108 | 19137.6 | 2.87064 | 2.54741 | 16.9827
PÅSTØP | PST-663(?) | Concrete-12850(?) | 18885.8 | 2.83287 | 2.43375 | 16.225

# IfcSlab: Floor:A254 - Avretting 45mm, Floor:A254 - Avretting 45mm:54035969
In: Nivå F
Type - PredefinedType: FLOOR; Material: T2_Mørtel 45 mm
ePset_LocationTool - Splitting: RESULT
ePset_Simplebim - Assembly Level: Leaf
AVINOR - 03_Ansvar: 72253; 08_Status: S4; 07_Fase: F90; 06_Omrade: TI; 02_Prosjekt: T20100; 05_ID-nummer: +TI=254.076; 01_Lufthavnkode: ENGM
Pset_SlabCommon - IsExternal: no; LoadBearing: no; Reference: A254 - Avretting 45mm
Pset_QuantityTakeOff - Reference: A254 - Avretting 45mm; sets with these values: 2
ePset_SimplebimBasicQuantities - Area, top, net (Simplebim): 62.9641 m2; Area, largest surface, net (Simplebim): 32.0059 m2; Thickness (Simplebim): 45 mm; Perimeter (Simplebim): 55331.3 mm; Volume, net (Simplebim): 2.83338 m3; Area, sides, net (Simplebim): 2.48991 m2

# IfcSlab: Floor:A254 - Installasjonsgulv - 45mm (2)
In: Nivå F
Type - PredefinedType: FLOOR; Material: T2_Installasjonsgulv 45 mm
ePset_LocationTool - Splitting: RESULT
AVINOR - 08_Status: S4; 07_Fase: F40; 05_ID-nummer: +TI=254.001; 06_Omrade: TI; 03_Ansvar: 72243; 02_Prosjekt: T20100; 01_Lufthavnkode: ENGM
Identity Data - CQFireRequirement: EI 60
ePset_SimplebimBasicQuantities - Thickness (Simplebim): 45 mm
ePset_Simplebim - Assembly Level: Leaf
Pset_SlabCommon - Reference: A254 - Installasjonsgulv - 45mm; IsExternal: no; LoadBearing: no
Pset_ReinforcementBarPitchOfSlab - Reference: A254 - Installasjonsgulv - 45mm; sets with these values: 2
Name (Floor:A254 - Installasjonsgulv - 45mm:...) | Area, sides, net (Simplebim) (m2) | Area, largest surface, net (Simplebim) (m2) | Perimeter (Simplebim) (mm) | Area, top, net (Simplebim) (m2) | Volume, net (Simplebim) (m3)
47994700 | 2.79342 | 77.8366 | 62076 | 79.0461 | 3.55707
47994700:2 | 1.57183 | 23.637 | 34929.7 | 24.2417 | 1.09088

# IfcSlab: Floor:A254 - Naturstein GU-N06 - Fauske marmor - 25mm inkl.lim, Floor:A254 - Naturstein GU-N06 - Fauske marmor - 25mm inkl.lim:56991841
In: Nivå F
Type - PredefinedType: FLOOR; Material: T2_Naturstein - 1-200 planer 20 mm, T2_Mørtel 5 mm
AVINOR - 05_ID-nummer: +TI=254.069; 08_Status: S4; 07_Fase: F90; 06_Omrade: TI; 02_Prosjekt: T20100; 03_Ansvar: 72235; 01_Lufthavnkode: ENGM
ePset_SimplebimBasicQuantities - Area, top, net (Simplebim): 23.8015 m2; Area, largest surface, net (Simplebim): 12.4332 m2; Perimeter (Simplebim): 40399.3 mm; Area, sides, net (Simplebim): 1.00998 m2; Volume, net (Simplebim): 0.595047 m3; Thickness (Simplebim): 25 mm
ePset_Simplebim - Assembly Level: Leaf
ePset_LocationTool - Splitting: RESULT
Pset_ReinforcementBarPitchOfSlab - Reference: A254 - Naturstein GU-N06 - Fauske marmor - 25mm inkl.lim; sets with these values: 2
Pset_SlabCommon - IsExternal: no; LoadBearing: no; Reference: A254 - Naturstein GU-N06 - Fauske marmor - 25mm inkl.lim

# IfcSlab: HD420 (16)
In: F
Description: HD420; PredefinedType: FLOOR
AVINOR - 08_Status: S4; 07_Fase: F40; 06_Omrade: TI; 04_Kontrakt: 72242; 03_Ansvar: 72242; 05_ID-nummer: +TI=251.025; 02_Prosjekt: T20100; 01_Lufthavnkode: ENGM
ePset_LocationTool - Splitting: RESULT
ePset_SimplebimBasicQuantities - Thickness (Simplebim): 420 mm
Tekla Common - Profile: HD420; Grade: C45/55; Name: HULLDEKKE; Class: 162
ePset_Simplebim - Assembly Level: Leaf
Pset_SlabCommon - LoadBearing: no
Name | Area, largest surface, net (Simplebim) (m2) | Perimeter (Simplebim) (mm) | Volume, net (Simplebim) (m3) | Area, sides, net (Simplebim) (m2) | Area, top, net (Simplebim) (m2) | Part mark = Reference | Assembly mark | Top elevation | Bottom elevation
HULLDEKKE | 2.54354 | 18609.1 | 0.507061 | 7.81582 | 3.69243 | HD-710 | HD-2283 | +210.680 | +210.260
4 x HULLDEKKE | 3.06678 | 22210.3 | 0.611372 | 9.32832 | 4.45202 | HD-734 | HD-2783 | +210.680 | +210.260
10 x HULLDEKKE | 3.06678 | 22210.3 | 0.611372 | 9.32832 | 4.45202 | HD-734 | HD-2783 | +210.530 | +210.110
HULLDEKKE | 2.54354 | 18609.2 | 0.507062 | 7.81585 | 3.69243 | HD-710 | HD-2283 | +210.680 | +210.260

# IfcSlab: TT600*2394-210-80-1266-0.05-0-0 (10)
In: F
Description: TT600*2394-210-80-1266-0.05-0-0; PredefinedType: FLOOR
AVINOR - 08_Status: S4; 07_Fase: F40; 05_ID-nummer: +TI=251.005; 06_Omrade: TI; 04_Kontrakt: 72242; 03_Ansvar: 72242; 02_Prosjekt: T20100; 01_Lufthavnkode: ENGM
ePset_LocationTool - Splitting: RESULT
ePset_SimplebimBasicQuantities - Thickness (Simplebim): 600 mm
ePset_Simplebim - Assembly Level: Leaf
Pset_SlabCommon - LoadBearing: no
Tekla Common - Name: DT; Grade: C45/55; Profile: TT600*2394-210-80-1266-0.05-0-0; Class: 164
Name | Area, largest surface, net (Simplebim) (m2) = Area, top, net (Simplebim) (m2) | Volume, net (Simplebim) (m3) | Area, sides, net (Simplebim) (m2) | Perimeter (Simplebim) (mm) | Reference = Part mark | Assembly mark | Bottom elevation | Top elevation
DT | 4.61735 | 1.00938 | 6.69461 | 11157.7 | Concrete-20124(?) | DT-533(?) | +210.080 | +210.680
DT | 11.3175 | 2.22035 | 12.8628 | 21438.1 | Concrete-3533(?) | DT-138(?) | +209.930 | +210.530
4 x DT | 13.167 | 2.40328 | 13.2082 | 22013.7 | Concrete-4369 | DT-214 | +209.930 | +210.530
3 x DT | 11.495 | 2.26952 | 13.1596 | 21932.6 | Concrete-3533 | DT-138 | +209.930 | +210.530
DT | 4.08069 | 1.00142 | 6.9713 | 11618.8 | Concrete-20124 | DT-533 | +210.080 | +210.680

# IfcSystem (14)
Name | Description
Trekkerør generelt | 4110 | MagiCAD Pset_System - Code: 4110; Description: Trekkerør generelt
Brannalarm | 542 | MagiCAD Pset_System - Code: 542; Description: Brannalarm
GULVKANAL | 4115 | MagiCAD Pset_System - Code: 4115; Description: GULVKANAL
Adgangskontroll, Innbruddsalarm | 543 | MagiCAD Pset_System - Code: 543; Description: Adgangskontroll, Innbruddsalarm
+TI=310.201-1 | +TI=310.201-1
+TD=313.028 | +TD=313.028
+TI=310.101-16 | +TI=310.101-16
+TI=313.001 | +TI=313.001
+TI=323.001 R | +TI=323.001 R
+TI=323.001 T | +TI=323.001 T
35= R 4° Kopi 2 | 35= R 4° Kopi 2
35= T 0° Kopi 2 | 35= T 0° Kopi 2
+TI=313.001-37 | +TI=313.001-37
+TI=332.001-NZ0006 | +TI=332.001-NZ0006

# IfcWall: 1000*1000 (2)
In: D
Description: 1000*1000; Material: CONCRETE/C35/45
Pset_WallCommon - LoadBearing: no; Reference: Concrete-14868(?)
ePset_LocationTool - Splitting: ORIGINAL
AVINOR - 08_Status: S4; 07_Fase: F90; 05_ID-nummer: +TI=241.001; 06_Omrade: TI; 04_Kontrakt: 72241; 02_Prosjekt: T20100; 03_Ansvar: 72101; 01_Lufthavnkode: ENGM
Tekla Quantity - AREA_NET: 6.6 m2; AREA_GROSS: 6.6 m2; Heigth: 1000 mm; Width: 1000 mm; Length: 1150 mm; WEIGTH_NET: 2760 kg; WEIGTH_GROSS: 2760 kg; VOLUME_NET: 1.15 m3; VOLUME_GROSS: 1.15 m3
ePset_SimplebimBasicQuantities - Height (Simplebim): 1000 mm; Thickness (Simplebim): 1000 mm; Length (Simplebim): 1150 mm; Area, side, gross, AABB (Simplebim): 1.15 m2; Area, side, gross, larger (Simplebim): 1.15 m2; Area, side, net, larger (Simplebim): 1.15 m2; Area, side, gross, smaller (Simplebim): 1.15 m2; Area, side, net, smaller (Simplebim): 1.15 m2; Area, largest surface, net (Simplebim): 1.15 m2; Area, side, net, average (Simplebim): 1.15 m2; Area, side, gross, average (Simplebim): 1.15 m2; Volume, net (Simplebim): 1.15 m3
ePset_Simplebim - Assembly Level: Leaf
Tekla Common - Name: PLASSTØPTVEGG; Profile: 1000*1000; Top elevation: +210.830; Bottom elevation: +209.680; Class: 250; Grade: C35/45; Part mark: Concrete-14868(?); Assembly mark: PLV-2483(?)

# IfcWall: 300*200 (5)
In: D
Description: 300*200; Material: CONCRETE/C35/45
ePset_SimplebimBasicQuantities - Thickness (Simplebim): 200 mm; Height (Simplebim): 300 mm
AVINOR - 08_Status: S4; 07_Fase: F90; 05_ID-nummer: +TI=241.001; 06_Omrade: TI; 04_Kontrakt: 72241; 02_Prosjekt: T20100; 03_Ansvar: 72101; 01_Lufthavnkode: ENGM
ePset_LocationTool - Splitting: ORIGINAL
Tekla Common - Name: PLASSTØPTVEGG; Class: 250; Grade: C35/45; Profile: 300*200
ePset_Simplebim - Assembly Level: Leaf
Pset_WallCommon - LoadBearing: no
Tekla Quantity - Width: 200 mm; Heigth: 300 mm
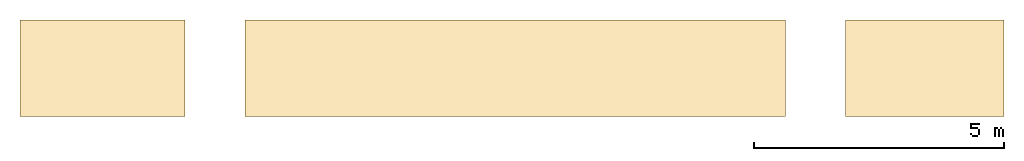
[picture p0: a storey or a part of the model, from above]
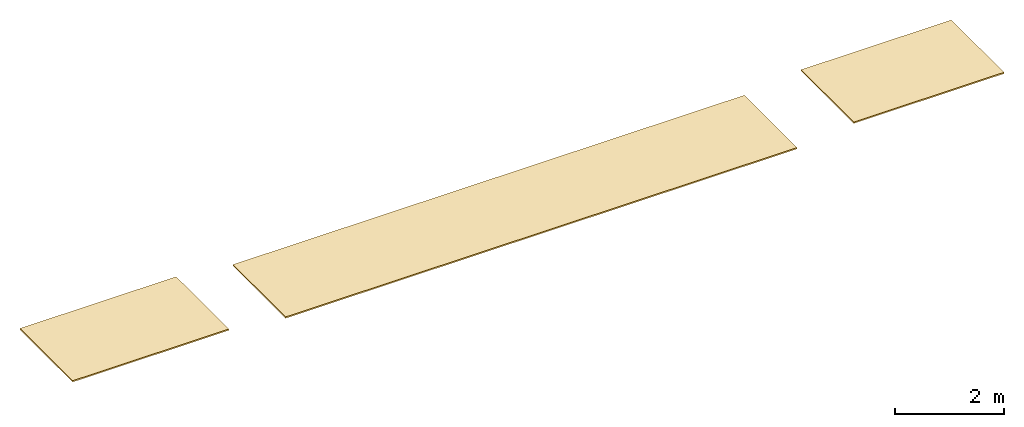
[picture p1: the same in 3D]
Properties of the parts of a building model (IFC2X3), part 3 of 3

# IfcWall: 300*200 (5)
Name | Length (Simplebim) (mm) | Volume, net (Simplebim) (m3) | Area, side, gross, AABB (Simplebim) (m2) = Area, side, gross, average (Simplebim) (m2) = Area, side, net, average (Simplebim) (m2) = Area, largest surface, net (Simplebim) (m2) = Area, side, net, larger (Simplebim) (m2) = Area, side, gross, larger (Simplebim) (m2) = Area, side, net, smaller (Simplebim) (m2) = Area, side, gross, smaller (Simplebim) (m2) | Top elevation | Bottom elevation | Part mark = Reference | Assembly mark | Length (mm) | WEIGTH_NET (kg) = WEIGTH_GROSS (kg) | AREA_NET (m2) = AREA_GROSS (m2) | VOLUME_NET (m3) = VOLUME_GROSS (m3)
PLASSTØPTVEGG | 12100.3 | 0.726019 | 3.63009 | +210.110 | +209.810 | Concrete-12903(?) | PLV-1355(?) | 12100.3 | 1742.44 | 12.2203 | 0.72602
PLASSTØPTVEGG | 2449.58 | 0.146975 | 0.734875 | +210.260 | +209.960 | Concrete-12902(?) | PLV-1355(?) | 2449.58 | 352.74 | 2.56958 | 0.14698
PLASSTØPTVEGG | 1000 | 0.0600001 | 0.300001 | +210.260 | +209.960 | Concrete-8387(?) | PLV-1380(?) | 1000 | 144 | 1.12 | 0.06
PLASSTØPTVEGG | 1000 | 0.0600001 | 0.300001 | +210.260 | +209.960 | Concrete-8387(?) | PLV-1381(?) | 1000 | 144 | 1.12 | 0.06
PLASSTØPTVEGG | 2449.58 | 0.146975 | 0.734875 | +210.260 | +209.960 | Concrete-12902(?) | PLV-1355(?) | 2450.11 | 352.815 | 2.57011 | 0.147

# IfcWall: 5330*250, PLASSTØPTVEGG
In: D
Description: 5330*250
Tekla Common - Bottom elevation: +205.180; Name: PLASSTØPTVEGG; Top elevation: +210.510; Part mark: Concrete-7481(?); Class: 250; Grade: C35/45; Assembly mark: PLV-1355(?); Profile: 5330*250
AVINOR - 08_Status: S4; 07_Fase: F90; 05_ID-nummer: +TI=241.001; 06_Omrade: TI; 04_Kontrakt: 72241; 02_Prosjekt: T20100; 03_Ansvar: 72101; 01_Lufthavnkode: ENGM
ePset_Simplebim - Assembly Level: Leaf
ePset_SimplebimBasicQuantities - Area, side, gross, AABB (Simplebim): 10.37 m2; Volume, net (Simplebim): 2.5925 m3; Area, side, net, average (Simplebim): 10.37 m2; Area, side, gross, average (Simplebim): 10.37 m2; Area, largest surface, net (Simplebim): 10.37 m2; Area, side, gross, larger (Simplebim): 10.37 m2; Area, side, net, larger (Simplebim): 10.37 m2; Area, side, gross, smaller (Simplebim): 10.37 m2; Area, side, net, smaller (Simplebim): 10.37 m2; Thickness (Simplebim): 250 mm; Height (Simplebim): 610 mm; Length (Simplebim): 17000 mm
ePset_LocationTool - Splitting: RESULT
Pset_WallCommon - Reference: Concrete-7481(?); LoadBearing: no

# IfcWall: Basic Wall:A245 - Butikkfasader bjelke/kasse (6)
Type - PredefinedType: STANDARD; Material: T2 - Stål 200 mm
Pset_ReinforcementBarPitchOfWall - Reference: A245 - Butikkfasader bjelke/kasse; sets with these values: 2
AVINOR - 08_Status: S4; 07_Fase: F90; 05_ID-nummer: +TI=245.051; 06_Omrade: TI; 03_Ansvar: 72717; 02_Prosjekt: T20100; 01_Lufthavnkode: ENGM
ePset_Simplebim - Assembly Level: Leaf
ePset_LocationTool - Splitting: RESULT
Pset_WallCommon - Reference: A245 - Butikkfasader bjelke/kasse; IsExternal: no; ExtendToStructure: no; LoadBearing: no
Name (Basic Wall:A245 - Butikkfasader bjelke/kasse:...) | In | Area, side, net, average (Simplebim) (m2) | Area, side, gross, average (Simplebim) (m2) | Area, side, gross, AABB (Simplebim) (m2) | Area, largest surface, net (Simplebim) (m2) | Area, side, gross, larger (Simplebim) (m2) | Area, side, net, larger (Simplebim) (m2) | Area, side, net, smaller (Simplebim) (m2) | Area, side, gross, smaller (Simplebim) (m2) | Thickness (Simplebim) (mm) | Height (Simplebim) (mm) | Length (Simplebim) (mm) | Volume, net (Simplebim) (m3)
58911262 | Nivå F | 2.60299 | 2.60299 | 2.6214 | 2.60299 | 2.60299 | 2.60299 | 2.60299 | 2.60299 | 200 | 300 | 8738 | 0.520598
58911262 | Nivå G - 2,0m | 1.73533 | 1.73533 | 1.7476 | 1.73533 | 1.73533 | 1.73533 | 1.73533 | 1.73533 | 200 | 200 | 8738 | 0.347065
61152719 | Nivå F | 0.124149 | 21.6366 | 0.5 | 0.5 | 21.6366 | 0.124149 | 0.124149 | 21.6366 | 49.6595 | 2500 | 200 | 0.0248297
58911261 | Nivå F | 2.60299 | 2.60299 | 2.6214 | 2.60299 | 2.60299 | 2.60299 | 2.60299 | 2.60299 | 200 | 300 | 8738 | 0.520598
58911261 | Nivå G - 2,0m | 1.73533 | 1.73533 | 1.7476 | 1.73533 | 1.73533 | 1.73533 | 1.73533 | 1.73533 | 200 | 200 | 8738 | 0.347065
61152597 | Nivå F | 0.950933 | 21.9134 | 21.99 | 0.903218 | 21.9899 | 1.02737 | 0.8745 | 21.837 | 200 | 2500 | 8796 | 0.190186

# IfcWallStandardCase: Basic Wall:A241 - SXV-100 (2)
Type - PredefinedType: STANDARD; Material: Plate - Gips 12.5 mm, _NSW X-finer 15 mm, _NSW Stålstender, uisolert 100 mm
Type - Pset_ReinforcementBarPitchOfWall - Description: 12,5mm Gipsplatter - 15mm X-finer - Stendervegg 100mm
ePset_LocationTool - Splitting: ORIGINAL
Pset_WallCommon - IsExternal: no; ExtendToStructure: no; LoadBearing: no; Reference: A241 - SXV-100
ePset_Simplebim - Assembly Level: Leaf
AVINOR - 03_Ansvar: 72253; 08_Status: S4; 07_Fase: F90; 05_ID-nummer: +TI=241.005; 06_Omrade: TI; 02_Prosjekt: T20100; 01_Lufthavnkode: ENGM
Pset_QuantityTakeOff - Reference: A241 - SXV-100; sets with these values: 2
ePset_SimplebimBasicQuantities - Thickness (Simplebim): 127.5 mm; Length (Simplebim): 5350.27 mm
Name (Basic Wall:A241 - SXV-100:...) | In | Area, side, gross, smaller (Simplebim) (m2) = Area, side, net, smaller (Simplebim) (m2) | Height (Simplebim) (mm) | Area, side, gross, average (Simplebim) (m2) = Area, side, net, average (Simplebim) (m2) | Area, side, gross, AABB (Simplebim) (m2) = Area, side, net, larger (Simplebim) (m2) = Area, side, gross, larger (Simplebim) (m2) = Area, largest surface, net (Simplebim) (m2) | Volume, net (Simplebim) (m3)
67879375 | Nivå F | 15.0044 | 2825 | 15.0595 | 15.1145 | 1.92008
67879375 | Nivå G - 2,0m | 1.05164 | 198 | 1.05549 | 1.05935 | 0.134576

# IfcWallStandardCase: Basic Wall:A241 - SXVXS-100 (2)
Type - PredefinedType: STANDARD; Material: Plate - Gips 13 mm, _NSW X-finer 12 mm, _NSW Stålstender, uisolert 100 mm, _NSW X-finer 12 mm, Plate - Gips 13 mm
Type - Pset_ReinforcementBarPitchOfWall - Description: Tilsvarende: T2 - IVEGG-125 - Forprosjekt
Type - Pset_WallCommon - AcousticRating: 37dB
ePset_LocationTool - Splitting: ORIGINAL
Pset_QuantityTakeOff - Reference: A241 - SXVXS-100; sets with these values: 2
ePset_Simplebim - Assembly Level: Leaf
ePset_SimplebimBasicQuantities - Length (Simplebim): 8348.01 mm; Thickness (Simplebim): 150 mm
Pset_WallCommon - IsExternal: no; ExtendToStructure: no; LoadBearing: no; Reference: A241 - SXVXS-100
AVINOR - 03_Ansvar: 72253; 08_Status: S4; 07_Fase: F90; 05_ID-nummer: +TI=241.005; 06_Omrade: TI; 02_Prosjekt: T20100; 01_Lufthavnkode: ENGM
Name (Basic Wall:A241 - SXVXS-100:...) | In | Area, side, net, average (Simplebim) (m2) = Area, side, gross, average (Simplebim) (m2) | Height (Simplebim) (mm) | Area, side, net, smaller (Simplebim) (m2) = Area, side, gross, smaller (Simplebim) (m2) | Volume, net (Simplebim) (m3) | Area, largest surface, net (Simplebim) (m2) = Area, side, net, larger (Simplebim) (m2) = Area, side, gross, larger (Simplebim) (m2) = Area, side, gross, AABB (Simplebim) (m2)
9757375 | Nivå F | 23.5184 | 2825 | 23.4536 | 3.52775 | 23.5831
9757375 | Nivå G - 2,0m | 1.64837 | 198 | 1.64383 | 0.247255 | 1.65291

# IfcWallStandardCase: Basic Wall:A245 - Butikkfasader bjelke/kasse (3)
Type - PredefinedType: STANDARD; Material: T2 - Stål 200 mm
Pset_ReinforcementBarPitchOfWall - Reference: A245 - Butikkfasader bjelke/kasse; sets with these values: 2
AVINOR - 08_Status: S4; 07_Fase: F90; 05_ID-nummer: +TI=245.051; 06_Omrade: TI; 03_Ansvar: 72717; 02_Prosjekt: T20100; 01_Lufthavnkode: ENGM
ePset_SimplebimBasicQuantities - Thickness (Simplebim): 200 mm
ePset_Simplebim - Assembly Level: Leaf
ePset_LocationTool - Splitting: ORIGINAL
Pset_WallCommon - Reference: A245 - Butikkfasader bjelke/kasse; IsExternal: no; ExtendToStructure: no; LoadBearing: no
Name (Basic Wall:A245 - Butikkfasader bjelke/kasse:...) | In | Area, side, gross, average (Simplebim) (m2) | Length (Simplebim) (mm) | Area, side, net, smaller (Simplebim) (m2) | Area, side, gross, smaller (Simplebim) (m2) | Area, side, net, average (Simplebim) (m2) | Height (Simplebim) (mm) | Volume, net (Simplebim) (m3) | Area, side, gross, larger (Simplebim) (m2) | Area, side, net, larger (Simplebim) (m2) | Area, largest surface, net (Simplebim) (m2) | Area, side, gross, AABB (Simplebim) (m2)
58911260 | Nivå F | 17.0627 | 19436.7 | 5.79434 | 17.0443 | 5.81268 | 300 | 1.16254 | 17.081 | 5.83102 | 5.83102 | 5.83102
58911260 | Nivå G - 2,0m | 15.1251 | 19436.7 | 3.86289 | 15.1129 | 3.87512 | 200 | 0.775024 | 15.1373 | 3.88735 | 3.88735 | 3.88735
61152778 | Nivå F | 45.25 | 18100 | 0.25 | 45.25 | 0.25 | 2500 | 0.05 | 45.25 | 0.25 | 0.5 | 45.25

# IfcWallStandardCase: Basic Wall:A245 - Gipsvegg, generisk (3)
Type - PredefinedType: STANDARD; Material: T2_Fibergips 200 mm
AVINOR - 08_Status: S4; 07_Fase: F90; 06_Omrade: TI; 05_ID-nummer: +TI=241.025; 03_Ansvar: 72717; 02_Prosjekt: T20100; 01_Lufthavnkode: ENGM
ePset_LocationTool - Splitting: ORIGINAL
Pset_WallCommon - Reference: A245 - Gipsvegg, generisk; IsExternal: no; ExtendToStructure: no; LoadBearing: no
Pset_QuantityTakeOff - Reference: A245 - Gipsvegg, generisk; sets with these values: 2
ePset_Simplebim - Assembly Level: Leaf
ePset_SimplebimBasicQuantities - Thickness (Simplebim): 200 mm
Name (Basic Wall:A245 - Gipsvegg, generisk:...) | In | Height (Simplebim) (mm) | Volume, net (Simplebim) (m3) | Length (Simplebim) (mm) | Area, side, gross, larger (Simplebim) (m2) = Area, side, net, larger (Simplebim) (m2) = Area, largest surface, net (Simplebim) (m2) = Area, side, gross, AABB (Simplebim) (m2) | Area, side, gross, smaller (Simplebim) (m2) = Area, side, net, smaller (Simplebim) (m2) | Area, side, net, average (Simplebim) (m2) = Area, side, gross, average (Simplebim) (m2)
69921906 | Nivå F | 2500 | 0.234005 | 468.011 | 1.17003 | 1.17003 | 1.17003
69922133 | Nivå F | 2800 | 0.130483 | 263.578 | 0.738019 | 0.56681 | 0.652415
69922133 | Nivå G - 2,0m | 200 | 0.00932021 | 263.578 | 0.0527157 | 0.0404864 | 0.046601
